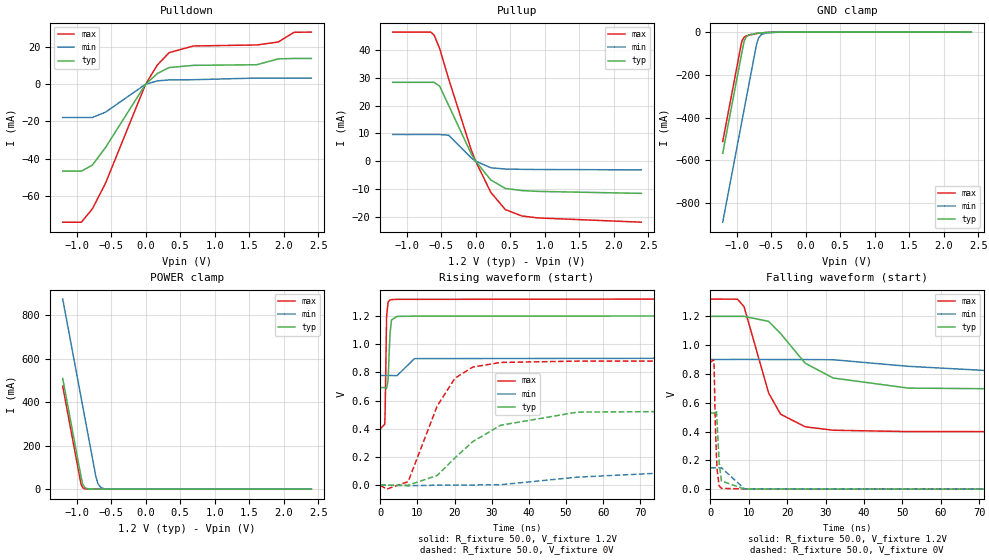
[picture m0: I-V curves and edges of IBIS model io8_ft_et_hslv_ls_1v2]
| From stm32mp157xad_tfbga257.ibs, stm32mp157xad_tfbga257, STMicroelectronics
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[Model]   io8_ft_et_hslv_ls_1v2
Model_type I/O
Polarity   Non-Inverting
Enable   Active-Low
| CAP_THRESHOLD on pad IOFT is "UDTCAPC" :
| Rising=20.00f vddiom   Falling=80.00f vddiom
| C_comp min and max val. don't necessarily correlate with the min and max pvt
| but are the smallest and greatest pad capacitance found.
| var   typ   min   max
C_comp   3.10945pF  3.08835pF  3.12935pF
|C_comp_pullup   1.82175pF  1.58940pF  1.75355pF
|C_comp_pulldown   1.28770pF  1.49895pF  1.37580pF
Vinl = 360.0mV
Vinh = 792.0mV
Vmeas = 600.0mV   | Reference voltage for timing measurements
Cref  = 50.0pF   | Timing specification test load capacitance value
Rref  = 100.0MOhm   | Timing specification test load resistance value
Vref  = 0V   | Timing specification test load voltage
[Model Spec]
| TIME_THRESHOLD on pin ZIV11 is "CMOS" :
| Rising=40.00f vdd   Falling=60.00f vdd
Vinl 463.60000mV 362.60000mV 506.60000mV
Vinh 741.40000mV 545.40000mV 817.40000mV
| variable   typ   min   max
[Temperature Range] 25.0 140.0 -40.0
| variable   typ   min   max
[Voltage Range] 1.2V 900.0mV 1.32V
| variable   typ   min   max
[POWER Clamp Reference] 1.2V 900.0mV 1.32V
| variable   typ   min   max
[GND Clamp Reference] 0V 0V 0V
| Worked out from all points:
|   slope of the pulldown table from 0 to 0.18 V, typ, clamps not added: 30 ohm
|   slope of the pullup table from 0 to 0.18 V, typ, clamps not added: 31.1 ohm
|   GND clamp passes 1 mA (typ) near -0.52 V on its own axis
|   POWER clamp passes 1 mA (typ) near -0.83 V on its own axis
|   rising waveform, R_fixture 50.0, V_fixture 1.2V: 20-80 % time 463ps typ, 1.28ns min, 297ps max; typ from 0.692 V to 1.2 V
|   falling waveform, R_fixture 50.0, V_fixture 1.2V: 20-80 % time 11.9ns typ, 29.9ns min, 6.05ns max; typ from 1.2 V to 0.692 V
|   rising waveform, R_fixture 50.0, V_fixture 0V: 20-80 % time 15.5ns typ, 35.5ns min, 8.51ns max; typ from 0 V to 0.529 V
|   falling waveform, R_fixture 50.0, V_fixture 0V: 20-80 % time 751ps typ, 1.47ns min, 598ps max; typ from 0.529 V to 0 V
[POWER Clamp]
-1.2V     508.8mA    874.1mA    473.5mA
-940mV    66.83mA    432.1mA    31.5mA
-930mV    49.83mA    415.1mA    19.15mA
-910mV    22.88mA    381.1mA    7.077mA
-880mV    7.117mA    330.1mA    1.59mA
-830mV    1.017mA    245.1mA    132uA
-720mV    14.05uA    58.12mA    554nA
-690mV    4.373uA    25.03mA    124.8nA
-650mV    922.5nA    8.136mA    17.23nA
-600mV    132.6nA    1.998mA    1.565nA
-490mV    2.857nA    90.92uA    111.8pA
2.4V      0A         0A         0A
[GND Clamp]
-1.2V     -567.2mA   -889.7mA   -512.2mA
-930mV    -108.2mA   -430.7mA   -53.23mA
-920mV    -91.21mA   -413.7mA   -40.49mA
-890mV    -43.51mA   -362.7mA   -23.59mA
-860mV    -22.57mA   -311.7mA   -17.89mA
-810mV    -12.11mA   -226.7mA   -13.23mA
-710mV    -6.053mA   -57.05mA   -7.064mA
-680mV    -4.908mA   -27.37mA   -5.632mA
-640mV    -3.605mA   -11.51mA   -3.985mA
-560mV    -1.665mA   -3.218mA   -1.61mA
-360mV    -34.72uA   -209.4uA   -9.248uA
2.4V      3.415nA    1.206uA    162.7pA
| variable   typ   min   max
[Pullup Reference] 1.2V 900.0mV 1.32V
| variable   typ   min   max
[Pulldown Reference] 0V 0V 0V
[Pullup]
-1.2V     28.34mA    9.569mA    46.41mA
-650mV    28.34mA    9.569mA    46.41mA
-600mV    28.34mA    9.569mA    45.32mA
-520mV    26.96mA    9.569mA    40.49mA
-390mV    20.06mA    9.313mA    29.59mA
-60mV     2.45mA     1.085mA    3.819mA
0V        5.9pA      1.254nA    2.839pA
220mV     -6.756mA   -2.387mA   -11.2mA
430mV     -9.815mA   -2.846mA   -17.42mA
670mV     -10.58mA   -2.948mA   -19.72mA
900mV     -10.88mA   -3.011mA   -20.42mA
2.4V      -11.6mA    -3.138mA   -21.96mA
[Pulldown]
-1.2V     -46.7mA    -17.86mA   -74.13mA
-930mV    -46.7mA    -17.86mA   -74.13mA
-770mV    -43.45mA   -17.86mA   -66.94mA
-580mV    -33.98mA   -14.99mA   -53.18mA
0V        0A         -6pA       0A
170mV     5.742mA    1.791mA    10.3mA
340mV     8.972mA    2.348mA    16.97mA
690mV     10.15mA    2.43mA     20.56mA
1.61V     10.49mA    3.332mA    21.11mA
1.92V     13.63mA    3.332mA    22.69mA
2.15V     13.87mA    3.332mA    27.93mA
2.4V      13.87mA    3.332mA    28.03mA
[Ramp]
dV/dt_r 317.3959mV/15.46923ns 89.16166mV/35.5467ns 528.12251mV/8.50615ns
dV/dt_f 304.64853mV/11.85118ns 73.17817mV/29.90312ns 552.41126mV/6.04586ns
R_load = 50.0
| Removed startup time: 0s 0s 0s  .
| Removed end time: 79.9ns.
[Rising Waveform]
R_fixture   = 50.0
V_fixture   = 1.2V
V_fixture_min = 900.0mV
V_fixture_max = 1.32V
0s        692.2mV    778.1mV    399.3mV
1.2ns     692.3mV    778.1mV    432.3mV
1.3ns     692.6mV    778.1mV    508.1mV
1.7ns     685.3mV    778.1mV    1.196V
2.1ns     745.8mV    778.1mV    1.299V
2.6ns     1.067V     778.1mV    1.313V
3ns       1.171V     778.1mV    1.316V
4.5ns     1.197V     776.4mV    1.318V
9.2ns     1.199V     897.5mV    1.318V
79.9ns    1.2V       899.9mV    1.32V
| Removed startup time: 0s 0s 0s  .
| Removed end time: 499.9ns.
[Falling Waveform]
R_fixture   = 50.0
V_fixture   = 1.2V
V_fixture_min = 900.0mV
V_fixture_max = 1.32V
0s        1.2V       900mV      1.32V
7.1ns     1.2V       900.8mV    1.319V
8.8ns     1.2V       901mV      1.267V
15.2ns    1.165V     900.1mV    666.7mV
18.3ns    1.081V     900mV      520.6mV
24.7ns    874.6mV    900mV      433.1mV
32ns      771.7mV    898.7mV    409.2mV
51.6ns    701.6mV    852.9mV    399.8mV
98.9ns    692.3mV    785.1mV    399.3mV
499.9ns   692.3mV    778mV      399.3mV
| Removed startup time: 0s 0s 0s  .
| Removed end time: 499.9ns.
[Rising Waveform]
R_fixture   = 50.0
V_fixture   = 0V
V_fixture_min = 0V
V_fixture_max = 0V
0s        -61.42nV   242.8nV    -3.809uV
1.7ns     -595.1uV   691.5nV    -28.55mV
7.5ns     -390.2uV   -4.45mV    24.63mV
15.3ns    68.29mV    -90.45uV   560.5mV
20.1ns    193.6mV    219.9uV    758.8mV
24.9ns    308.6mV    746.1uV    837.6mV
32.4ns    424.9mV    3.163mV    870.5mV
53.1ns    518.2mV    56.75mV    879.8mV
121.9ns   528.8mV    145.6mV    880.2mV
499.9ns   529mV      148.6mV    880.2mV
| Removed startup time: 0s 0s 0s  .
| Removed end time: 79.9ns.
[Falling Waveform]
R_fixture   = 50.0
V_fixture   = 0V
V_fixture_min = 0V
V_fixture_max = 0V
0s        529mV      148.7mV    880.2mV
900ps     529.3mV    148.7mV    898.7mV
1ns       529.1mV    148.7mV    852.4mV
1.3ns     533mV      148.7mV    460.6mV
1.6ns     547.2mV    148.7mV    235mV
1.8ns     453.4mV    148.7mV    131.1mV
2.3ns     189.2mV    148.7mV    23.75mV
2.9ns     57.04mV    148.6mV    6.151mV
8.9ns     813.1uV    2.608mV    1.267mV
79.9ns    4.406uV    42.18uV    -4.568uV
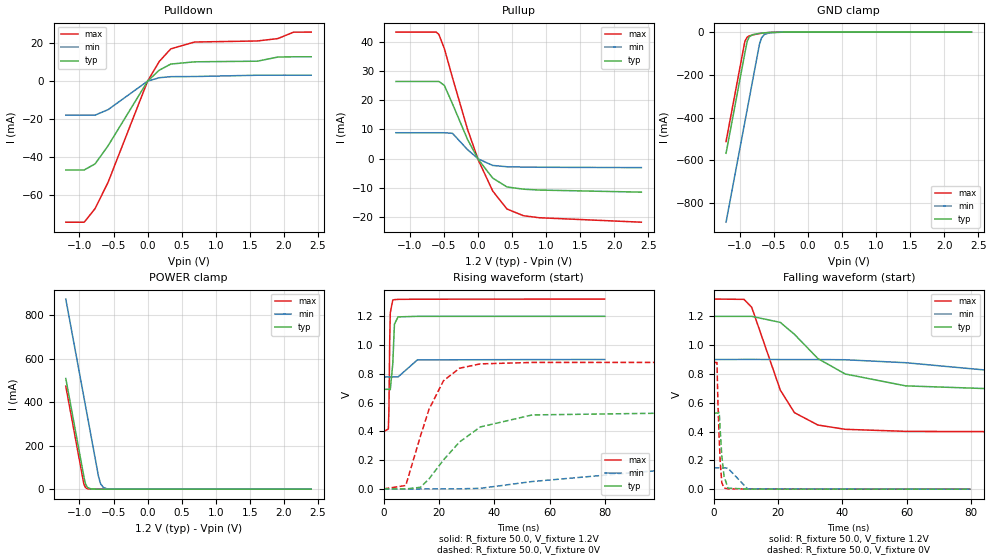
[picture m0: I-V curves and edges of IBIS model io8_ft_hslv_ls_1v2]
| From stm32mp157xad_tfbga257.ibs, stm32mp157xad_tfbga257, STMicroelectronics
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[Model]   io8_ft_hslv_ls_1v2
Model_type I/O
Polarity   Non-Inverting
Enable   Active-Low
| CAP_THRESHOLD on pad IOFT is "UDTCAPC" :
| Rising=20.00f vddiom   Falling=80.00f vddiom
| C_comp min and max val. don't necessarily correlate with the min and max pvt
| but are the smallest and greatest pad capacitance found.
| var   typ   min   max
C_comp   3.08865pF  3.06550pF  3.10825pF
|C_comp_pullup   1.81640pF  1.58310pF  1.74795pF
|C_comp_pulldown   1.27225pF  1.48240pF  1.36030pF
Vinl = 360.0mV
Vinh = 792.0mV
Vmeas = 600.0mV   | Reference voltage for timing measurements
Cref  = 50.0pF   | Timing specification test load capacitance value
Rref  = 100.0MOhm   | Timing specification test load resistance value
Vref  = 0V   | Timing specification test load voltage
[Model Spec]
| TIME_THRESHOLD on pin ZIV11 is "CMOS" :
| Rising=40.00f vdd   Falling=60.00f vdd
Vinl 463.60000mV 362.60000mV 506.60000mV
Vinh 741.40000mV 545.40000mV 817.40000mV
| variable   typ   min   max
[Temperature Range] 25.0 140.0 -40.0
| variable   typ   min   max
[Voltage Range] 1.2V 900.0mV 1.32V
| variable   typ   min   max
[POWER Clamp Reference] 1.2V 900.0mV 1.32V
| variable   typ   min   max
[GND Clamp Reference] 0V 0V 0V
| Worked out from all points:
|   slope of the pulldown table from 0 to 0.18 V, typ, clamps not added: 30 ohm
|   slope of the pullup table from 0 to 0.18 V, typ, clamps not added: 31.1 ohm
|   GND clamp passes 1 mA (typ) near -0.52 V on its own axis
|   POWER clamp passes 1 mA (typ) near -0.83 V on its own axis
|   rising waveform, R_fixture 50.0, V_fixture 1.2V: 20-80 % time 598ps typ, 1.65ns min, 350ps max; typ from 0.692 V to 1.2 V
|   falling waveform, R_fixture 50.0, V_fixture 1.2V: 20-80 % time 17.6ns typ, 43.1ns min, 8.86ns max; typ from 1.2 V to 0.692 V
|   rising waveform, R_fixture 50.0, V_fixture 0V: 20-80 % time 16.2ns typ, 35.6ns min, 9.39ns max; typ from 0 V to 0.528 V
|   falling waveform, R_fixture 50.0, V_fixture 0V: 20-80 % time 1.12ns typ, 2.35ns min, 846ps max; typ from 0.528 V to 0 V
[POWER Clamp]
-1.2V     508.8mA    874.1mA    473.5mA
-940mV    66.83mA    432.1mA    31.5mA
-930mV    49.83mA    415.1mA    19.15mA
-910mV    22.88mA    381.1mA    7.077mA
-880mV    7.117mA    330.1mA    1.59mA
-830mV    1.017mA    245.1mA    132uA
-720mV    14.05uA    58.12mA    554nA
-690mV    4.373uA    25.03mA    124.7nA
-650mV    922.4nA    8.136mA    17.22nA
-600mV    132.5nA    1.998mA    1.555nA
-490mV    2.736nA    90.9uA     103pA
2.4V      0A         0A         0A
[GND Clamp]
-1.2V     -567.2mA   -889.7mA   -512.2mA
-930mV    -108.2mA   -430.7mA   -53.23mA
-920mV    -91.21mA   -413.7mA   -40.49mA
-890mV    -43.51mA   -362.7mA   -23.59mA
-860mV    -22.57mA   -311.7mA   -17.89mA
-810mV    -12.11mA   -226.7mA   -13.23mA
-710mV    -6.053mA   -57.05mA   -7.064mA
-680mV    -4.908mA   -27.37mA   -5.632mA
-640mV    -3.605mA   -11.51mA   -3.985mA
-560mV    -1.665mA   -3.218mA   -1.61mA
-360mV    -34.72uA   -209.4uA   -9.248uA
2.4V      3.381nA    1.198uA    162.5pA
| variable   typ   min   max
[Pullup Reference] 1.2V 900.0mV 1.32V
| variable   typ   min   max
[Pulldown Reference] 0V 0V 0V
[Pullup]
-1.2V     26.54mA    8.882mA    43.55mA
-610mV    26.54mA    8.882mA    43.55mA
-570mV    26.54mA    8.882mA    42.74mA
-490mV    25.2mA     8.882mA    37.91mA
-370mV    18.81mA    8.672mA    27.82mA
-150mV    6.588mA    3.069mA    10.09mA
10mV      -383.3uA   -162.1uA   -605.9uA
220mV     -6.749mA   -2.383mA   -11.2mA
430mV     -9.803mA   -2.841mA   -17.41mA
670mV     -10.56mA   -2.943mA   -19.69mA
900mV     -10.86mA   -3.006mA   -20.39mA
2.4V      -11.58mA   -3.133mA   -21.93mA
[Pulldown]
-1.2V     -46.7mA    -17.86mA   -74.13mA
-930mV    -46.7mA    -17.86mA   -74.13mA
-770mV    -43.45mA   -17.86mA   -66.94mA
-580mV    -33.98mA   -14.99mA   -53.18mA
0V        0A         -3pA       0A
170mV     5.742mA    1.791mA    10.3mA
340mV     8.972mA    2.348mA    16.97mA
690mV     10.15mA    2.43mA     20.56mA
1.61V     10.49mA    3.107mA    21.11mA
1.91V     12.66mA    3.107mA    22.36mA
2.14V     12.8mA     3.107mA    25.73mA
2.4V      12.8mA     3.107mA    25.78mA
[Ramp]
dV/dt_r 316.98204mV/16.17336ns 89.01707mV/35.60268ns 527.833mV/9.39272ns
dV/dt_f 304.64461mV/17.62369ns 73.17368mV/43.1129ns 552.4115mV/8.85601ns
R_load = 50.0
| Removed startup time: 0s 0s 0s  .
| Removed end time: 79.9ns.
[Rising Waveform]
R_fixture   = 50.0
V_fixture   = 1.2V
V_fixture_min = 900.0mV
V_fixture_max = 1.32V
0s        692.2mV    778.1mV    399.3mV
1.7ns     692.4mV    778.1mV    416.2mV
1.9ns     692.3mV    778.1mV    539.1mV
2.2ns     691.5mV    778.1mV    1.04V
2.4ns     689.8mV    778.1mV    1.225V
3.3ns     871.2mV    778.1mV    1.313V
3.9ns     1.145V     778.1mV    1.316V
5.2ns     1.196V     778.1mV    1.318V
12.2ns    1.2V       897.2mV    1.319V
79.9ns    1.2V       899.9mV    1.32V
| Removed startup time: 0s 0s 0s  .
| Removed end time: 499.9ns.
[Falling Waveform]
R_fixture   = 50.0
V_fixture   = 1.2V
V_fixture_min = 900.0mV
V_fixture_max = 1.32V
0s        1.2V       900mV      1.32V
9.4ns     1.2V       900.8mV    1.318V
11.8ns    1.2V       900.9mV    1.263V
20.7ns    1.158V     900mV      687.9mV
25.1ns    1.075V     900mV      531.3mV
32.4ns    906.7mV    900mV      445.3mV
40.9ns    799.8mV    898.6mV    415.6mV
59.7ns    717.3mV    878mV      401.4mV
88.5ns    695.4mV    819.1mV    399.3mV
499.9ns   692.3mV    778mV      399.3mV
| Removed startup time: 0s 0s 0s  .
| Removed end time: 499.9ns.
[Rising Waveform]
R_fixture   = 50.0
V_fixture   = 0V
V_fixture_min = 0V
V_fixture_max = 0V
0s        73.05nV    737.4nV    -2.39uV
8ns       -430.3uV   -1.995mV   23.65mV
13.3ns    11.11mV    -432.9uV   366.8mV
16.4ns    69.31mV    -106.5uV   553.2mV
21.6ns    200.4mV    117.8uV    751.1mV
27.4ns    325.7mV    452.4uV    838.8mV
34.9ns    430.3mV    3.669mV    869.2mV
53.7ns    514.2mV    51.17mV    879.2mV
107ns     528.1mV    140.6mV    879.7mV
499.9ns   528.3mV    148.4mV    879.7mV
| Removed startup time: 0s 0s 0s  .
| Removed end time: 79.9ns.
[Falling Waveform]
R_fixture   = 50.0
V_fixture   = 0V
V_fixture_min = 0V
V_fixture_max = 0V
0s        528.3mV    148.4mV    879.7mV
1ns       528.4mV    148.4mV    879.3mV
1.3ns     528mV      148.4mV    593.2mV
1.7ns     532.9mV    148.4mV    343.6mV
2ns       410.7mV    148.4mV    190.2mV
2.5ns     229.7mV    148.4mV    45.74mV
3.2ns     90.24mV    148.3mV    7.314mV
4.4ns     7.202mV    145.6mV    2.088mV
10.5ns    594.3uV    2.606mV    1.234mV
79.9ns    5.325uV    82.6uV     42.19nV
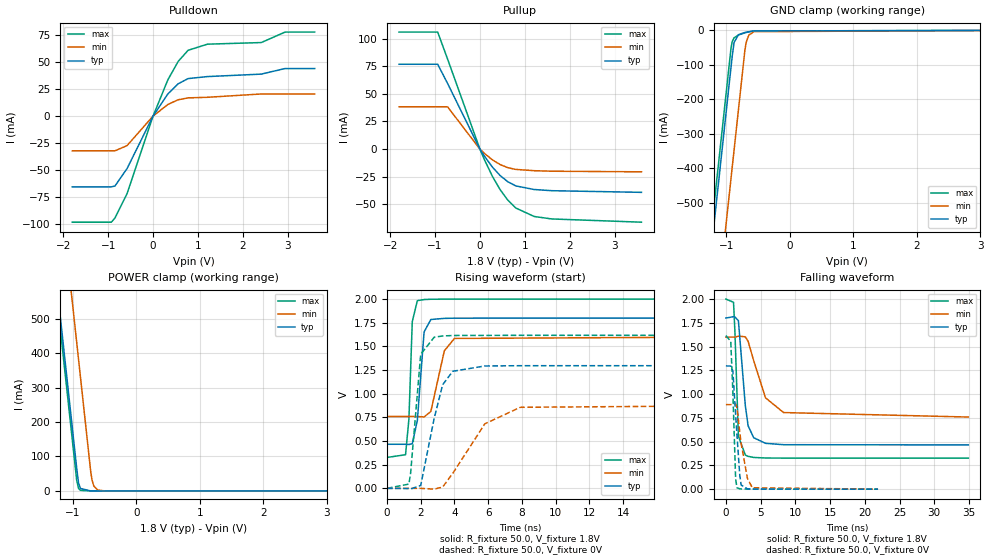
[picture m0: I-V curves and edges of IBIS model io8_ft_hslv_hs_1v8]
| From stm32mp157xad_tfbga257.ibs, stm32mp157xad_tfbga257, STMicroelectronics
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[Model]   io8_ft_hslv_hs_1v8
Model_type I/O
Polarity   Non-Inverting
Enable   Active-Low
| CAP_THRESHOLD on pad IOFT is "UDTCAPC" :
| Rising=20.00f vddiom   Falling=80.00f vddiom
| C_comp min and max val. don't necessarily correlate with the min and max pvt
| but are the smallest and greatest pad capacitance found.
| var   typ   min   max
C_comp   3.40998pF  3.40231pF  3.47825pF
|C_comp_pullup   1.96225pF  2.05415pF  1.91340pF
|C_comp_pulldown   1.44773pF  1.34816pF  1.56485pF
Vinl = 640.0mV
Vinh = 1.2V
Vmeas = 900.0mV   | Reference voltage for timing measurements
Cref  = 50.0pF   | Timing specification test load capacitance value
Rref  = 100.0MOhm   | Timing specification test load resistance value
Vref  = 0V   | Timing specification test load voltage
[Model Spec]
| TIME_THRESHOLD on pin ZIV11 is "CMOS" :
| Rising=40.00f vdd   Falling=60.00f vdd
Vinl 738.60000mV 665.60000mV 824.60000mV
Vinh 1.04640V 924.40000mV 1.13940V
| variable   typ   min   max
[Temperature Range] 25.0 140.0 -40.0
| variable   typ   min   max
[Voltage Range] 1.8V 1.6V 2.0V
| variable   typ   min   max
[POWER Clamp Reference] 1.8V 1.6V 2.0V
| variable   typ   min   max
[GND Clamp Reference] 0V 0V 0V
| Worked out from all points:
|   slope of the pulldown table from 0 to 0.27 V, typ, clamps not added: 16 ohm
|   slope of the pullup table from 0 to 0.27 V, typ, clamps not added: 17 ohm
|   GND clamp passes 1 mA (typ) near -0.52 V on its own axis
|   POWER clamp passes 1 mA (typ) near -0.83 V on its own axis
|   rising waveform, R_fixture 50.0, V_fixture 1.8V: 20-80 % time 316ps typ, 577ps min, 206ps max; typ from 0.466 V to 1.8 V
|   falling waveform, R_fixture 50.0, V_fixture 1.8V: 20-80 % time 895ps typ, 2.28ns min, 428ps max; typ from 1.8 V to 0.466 V
|   rising waveform, R_fixture 50.0, V_fixture 0V: 20-80 % time 886ps typ, 2.03ns min, 434ps max; typ from 0 V to 1.3 V
|   falling waveform, R_fixture 50.0, V_fixture 0V: 20-80 % time 706ps typ, 1.07ns min, 422ps max; typ from 1.3 V to 0 V
[POWER Clamp]
-1.8V     1.529A     1.894A     1.494A
-940mV    66.83mA    432.1mA    31.5mA
-910mV    22.88mA    381.1mA    7.077mA
-880mV    7.117mA    330.1mA    1.59mA
-720mV    14.05uA    58.12mA    554nA
-700mV    6.453uA    33.14mA    205nA
-670mV    2.008uA    14.27mA    46.28nA
-610mV    195.3nA    2.645mA    2.496nA
-500mV    3.825nA    120.4uA    129.9pA
3.6V      0A         0A         0A
[GND Clamp]
-1.8V     -1.588A    -1.91A     -1.533A
-1.26V    -670.3mA   -992.4mA   -614.9mA
-1.2V     -568.3mA   -890.4mA   -512.9mA
-930mV    -109.3mA   -431.4mA   -53.86mA
-910mV    -75.33mA   -397.4mA   -32.91mA
-880mV    -34.88mA   -346.4mA   -21.56mA
-810mV    -12.56mA   -227.4mA   -13.55mA
-710mV    -6.275mA   -57.63mA   -7.234mA
-690mV    -5.461mA   -35.21mA   -6.234mA
-650mV    -4.039mA   -14.43mA   -4.463mA
-570mV    -1.908mA   -3.832mA   -1.869mA
3.6V      5.036nA    1.588uA    245.5pA
| variable   typ   min   max
[Pullup Reference] 1.8V 1.6V 2.0V
| variable   typ   min   max
[Pulldown Reference] 0V 0V 0V
[Pullup]
-1.8V     76.86mA    38.28mA    106mA
-940mV    76.86mA    38.28mA    106mA
-720mV    59.49mA    38.28mA    81.6mA
0V        7.41pA     1.331nA    4.294pA
100mV     -6.394mA   -3.908mA   -9.529mA
280mV     -16.38mA   -9.808mA   -24.78mA
450mV     -23.93mA   -14.01mA   -36.72mA
620mV     -29.56mA   -16.84mA   -46.16mA
800mV     -33.39mA   -18.42mA   -53.41mA
1.21V     -36.65mA   -19.59mA   -61.09mA
1.6V      -37.71mA   -20.06mA   -63.31mA
3.6V      -39.21mA   -20.61mA   -66.25mA
[Pulldown]
-1.8V     -65.8mA    -32.31mA   -98.64mA
-930mV    -65.8mA    -32.31mA   -98.64mA
-850mV    -65.04mA   -32.31mA   -94.81mA
-580mV    -48.83mA   -27.49mA   -72.14mA
0V        0A         -2pA       0A
330mV     20.59mA    10.79mA    33.74mA
560mV     30.02mA    15.15mA    50.81mA
780mV     34.81mA    16.9mA     61.1mA
1.21V     36.69mA    17.44mA    66.81mA
2.41V     38.98mA    20.52mA    68.31mA
2.94V     44.17mA    20.52mA    78.04mA
3.6V      44.17mA    20.52mA    78.04mA
[Ramp]
dV/dt_r 777.74202mV/885.08357ps 533.91629mV/2.02828ns 970.01067mV/429.38377ps
dV/dt_f 800.5976mV/890.36148ps 504.71888mV/2.27422ns 1.00395V/423.14642ps
R_load = 50.0
| Removed startup time: 0s 0s 0s  .
| Removed end time: 21.9ns.
[Rising Waveform]
R_fixture   = 50.0
V_fixture   = 1.8V
V_fixture_min = 1.6V
V_fixture_max = 2.0V
0s        465.7mV    758.8mV    326.7mV
1.1ns     465.8mV    759mV      355.2mV
1.3ns     463.2mV    759.1mV    730.7mV
1.5ns     471.9mV    759.2mV    1.762V
1.8ns     717.3mV    759.1mV    1.983V
2.2ns     1.653V     754.3mV    1.995V
2.6ns     1.784V     812.9mV    1.998V
3.4ns     1.796V     1.453V     1.999V
4ns       1.798V     1.584V     2V
21.9ns    1.8V       1.6V       2V
| Removed startup time: 0s 0s 0s  .
| Removed end time: 34.9ns.
[Falling Waveform]
R_fixture   = 50.0
V_fixture   = 1.8V
V_fixture_min = 1.6V
V_fixture_max = 2.0V
0s        1.8V       1.6V       2V
1.1ns     1.815V     1.6V       1.966V
1.3ns     1.811V     1.599V     1.654V
1.8ns     1.773V     1.61V      557.6mV
2.8ns     875.8mV    1.603V     358.7mV
3.2ns     666.1mV    1.555V     345.3mV
4ns       541.4mV    1.352V     333.8mV
5.7ns     482.3mV    961.3mV    327.8mV
8.3ns     467.8mV    806mV      326.8mV
34.9ns    465.7mV    758.8mV    326.8mV
| Removed startup time: 0s 0s 0s  .
| Removed end time: 34.9ns.
[Rising Waveform]
R_fixture   = 50.0
V_fixture   = 0V
V_fixture_min = 0V
V_fixture_max = 0V
0s        -22.87nV   119.6nV    -3.298uV
1.3ns     -1.671mV   -9.335uV   45.23mV
1.4ns     -6.977mV   -4.753uV   159mV
2ns       31.03mV    90.39uV    1.417V
2.8ns     741.3mV    -8.512mV   1.597V
3.3ns     1.095V     14.41mV    1.61V
3.9ns     1.237V     158.7mV    1.615V
5.8ns     1.293V     682mV      1.616V
7.9ns     1.296V     856.5mV    1.617V
34.9ns    1.296V     889.9mV    1.617V
| Removed startup time: 0s 0s 0s  .
| Removed end time: 21.9ns.
[Falling Waveform]
R_fixture   = 50.0
V_fixture   = 0V
V_fixture_min = 0V
V_fixture_max = 0V
0s        1.296V     889.9mV    1.617V
700ps     1.296V     889.9mV    1.555V
1ns       1.246V     889.9mV    1.028V
1.4ns     784.2mV    895.2mV    109.3mV
1.6ns     564.9mV    854.1mV    14.39mV
2ns       143.6mV    600.5mV    3.632mV
2.2ns     43.47mV    478.9mV    2.733mV
3.1ns     3.072mV    114.6mV    980.4uV
3.8ns     1.612mV    14.47mV    494.6uV
21.9ns    1.333uV    6.536uV    200.7nV
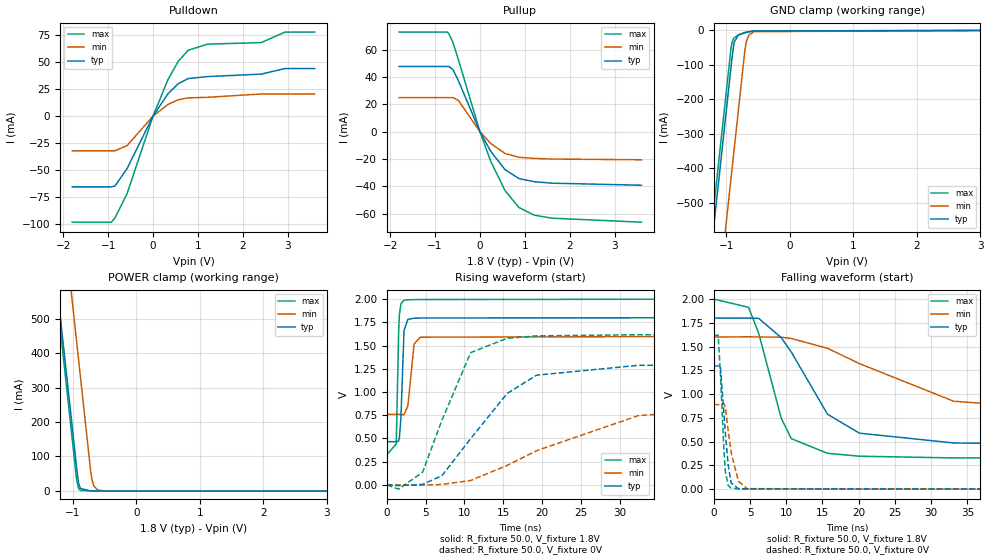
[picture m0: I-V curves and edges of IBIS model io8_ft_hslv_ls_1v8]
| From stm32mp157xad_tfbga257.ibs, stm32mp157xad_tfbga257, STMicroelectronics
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[Model]   io8_ft_hslv_ls_1v8
Model_type I/O
Polarity   Non-Inverting
Enable   Active-Low
| CAP_THRESHOLD on pad IOFT is "UDTCAPC" :
| Rising=20.00f vddiom   Falling=80.00f vddiom
| C_comp min and max val. don't necessarily correlate with the min and max pvt
| but are the smallest and greatest pad capacitance found.
| var   typ   min   max
C_comp   3.40998pF  3.40231pF  3.47825pF
|C_comp_pullup   1.96225pF  2.05415pF  1.91340pF
|C_comp_pulldown   1.44773pF  1.34816pF  1.56485pF
Vinl = 640.0mV
Vinh = 1.2V
Vmeas = 900.0mV   | Reference voltage for timing measurements
Cref  = 50.0pF   | Timing specification test load capacitance value
Rref  = 100.0MOhm   | Timing specification test load resistance value
Vref  = 0V   | Timing specification test load voltage
[Model Spec]
| TIME_THRESHOLD on pin ZIV11 is "CMOS" :
| Rising=40.00f vdd   Falling=60.00f vdd
Vinl 738.60000mV 665.60000mV 824.60000mV
Vinh 1.04640V 924.40000mV 1.13940V
| variable   typ   min   max
[Temperature Range] 25.0 140.0 -40.0
| variable   typ   min   max
[Voltage Range] 1.8V 1.6V 2.0V
| variable   typ   min   max
[POWER Clamp Reference] 1.8V 1.6V 2.0V
| variable   typ   min   max
[GND Clamp Reference] 0V 0V 0V
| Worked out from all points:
|   slope of the pulldown table from 0 to 0.27 V, typ, clamps not added: 16 ohm
|   slope of the pullup table from 0 to 0.27 V, typ, clamps not added: 17 ohm
|   GND clamp passes 1 mA (typ) near -0.52 V on its own axis
|   POWER clamp passes 1 mA (typ) near -0.83 V on its own axis
|   rising waveform, R_fixture 50.0, V_fixture 1.8V: 20-80 % time 290ps typ, 520ps min, 237ps max; typ from 0.466 V to 1.8 V
|   falling waveform, R_fixture 50.0, V_fixture 1.8V: 20-80 % time 6.49ns typ, 15.7ns min, 3.61ns max; typ from 1.8 V to 0.466 V
|   rising waveform, R_fixture 50.0, V_fixture 0V: 20-80 % time 7.46ns typ, 15.8ns min, 4.19ns max; typ from 0 V to 1.3 V
|   falling waveform, R_fixture 50.0, V_fixture 0V: 20-80 % time 807ps typ, 1.14ns min, 598ps max; typ from 1.3 V to 0 V
[POWER Clamp]
-1.8V     1.529A     1.894A     1.494A
-940mV    66.83mA    432.1mA    31.5mA
-910mV    22.88mA    381.1mA    7.077mA
-880mV    7.117mA    330.1mA    1.59mA
-720mV    14.05uA    58.12mA    554nA
-700mV    6.453uA    33.14mA    205nA
-670mV    2.008uA    14.27mA    46.28nA
-610mV    195.3nA    2.645mA    2.496nA
-500mV    3.825nA    120.4uA    129.9pA
3.6V      0A         0A         0A
[GND Clamp]
-1.8V     -1.588A    -1.91A     -1.533A
-1.26V    -670.3mA   -992.4mA   -614.9mA
-1.2V     -568.3mA   -890.4mA   -512.9mA
-930mV    -109.3mA   -431.4mA   -53.86mA
-910mV    -75.33mA   -397.4mA   -32.91mA
-880mV    -34.88mA   -346.4mA   -21.56mA
-810mV    -12.56mA   -227.4mA   -13.55mA
-710mV    -6.275mA   -57.63mA   -7.234mA
-690mV    -5.461mA   -35.21mA   -6.234mA
-650mV    -4.039mA   -14.43mA   -4.463mA
-570mV    -1.908mA   -3.832mA   -1.869mA
3.6V      5.036nA    1.588uA    245.5pA
| variable   typ   min   max
[Pullup Reference] 1.8V 1.6V 2.0V
| variable   typ   min   max
[Pulldown Reference] 0V 0V 0V
[Pullup]
-1.8V     47.63mA    24.9mA     72.78mA
-730mV    47.63mA    24.9mA     72.78mA
-690mV    47.63mA    24.9mA     71.57mA
-600mV    45.37mA    24.9mA     65.1mA
-480mV    37.34mA    22.87mA    52.75mA
0V        7.41pA     1.331nA    4.294pA
240mV     -14.34mA   -8.624mA   -21.61mA
560mV     -27.8mA    -16mA      -43.11mA
870mV     -34.35mA   -18.76mA   -55.49mA
1.21V     -36.65mA   -19.59mA   -61.09mA
1.6V      -37.71mA   -20.06mA   -63.31mA
3.6V      -39.21mA   -20.61mA   -66.25mA
[Pulldown]
-1.8V     -65.8mA    -32.31mA   -98.64mA
-930mV    -65.8mA    -32.31mA   -98.64mA
-850mV    -65.04mA   -32.31mA   -94.81mA
-580mV    -48.83mA   -27.49mA   -72.14mA
0V        0A         -2pA       0A
330mV     20.59mA    10.79mA    33.74mA
560mV     30.02mA    15.15mA    50.81mA
780mV     34.81mA    16.9mA     61.1mA
1.21V     36.69mA    17.44mA    66.81mA
2.41V     38.98mA    20.51mA    68.31mA
2.94V     44.17mA    20.51mA    78.04mA
3.6V      44.17mA    20.51mA    78.04mA
[Ramp]
dV/dt_r 777.75174mV/7.46009ns 533.88892mV/15.81359ns 970.01446mV/4.19376ns
dV/dt_f 800.59769mV/6.48971ns 504.70755mV/15.73502ns 1.00395V/3.60949ns
R_load = 50.0
| Removed startup time: 0s 0s 0s  .
| Removed end time: 54.9ns.
[Rising Waveform]
R_fixture   = 50.0
V_fixture   = 1.8V
V_fixture_min = 1.6V
V_fixture_max = 2.0V
0s        465.7mV    758.8mV    326.7mV
1.2ns     465.2mV    758.9mV    441.8mV
1.5ns     472.5mV    759mV      1.629V
1.6ns     505.3mV    758.9mV    1.829V
1.8ns     717.4mV    758.7mV    1.95V
2.2ns     1.662V     754.7mV    1.987V
2.7ns     1.782V     853.7mV    1.992V
3.5ns     1.794V     1.517V     1.994V
4.3ns     1.796V     1.59V      1.995V
54.9ns    1.8V       1.6V       2V
| Removed startup time: 0s 0s 0s  .
| Removed end time: 364.9ns.
[Falling Waveform]
R_fixture   = 50.0
V_fixture   = 1.8V
V_fixture_min = 1.6V
V_fixture_max = 2.0V
0s        1.8V       1.6V       2V
4.8ns     1.8V       1.603V     1.913V
6.2ns     1.797V     1.601V     1.64V
9.3ns     1.595V     1.599V     748.8mV
10.7ns    1.442V     1.585V     531.3mV
15.7ns    788mV      1.482V     377.3mV
20.1ns    589.1mV    1.321V     346.8mV
33.1ns    486.2mV    925.2mV    328.7mV
58.4ns    466.8mV    781.8mV    326.8mV
364.9ns   465.7mV    758.8mV    326.7mV
| Removed startup time: 0s 0s 0s  .
| Removed end time: 364.9ns.
[Rising Waveform]
R_fixture   = 50.0
V_fixture   = 0V
V_fixture_min = 0V
V_fixture_max = 0V
0s        121.1nV    205.2nV    -3.013uV
1.5ns     -7.557mV   5.524uV    -45.43mV
4.6ns     5.784mV    -1.439mV   137.6mV
7.1ns     100.5mV    5.302mV    698.5mV
10.8ns    498.3mV    48.08mV    1.424V
15.5ns    984mV      209.7mV    1.578V
19.3ns    1.181V     368.8mV    1.604V
32.4ns    1.287V     745.1mV    1.616V
51.8ns    1.296V     872.9mV    1.617V
364.9ns   1.296V     889.8mV    1.617V
| Removed startup time: 0s 0s 0s  .
| Removed end time: 54.9ns.
[Falling Waveform]
R_fixture   = 50.0
V_fixture   = 0V
V_fixture_min = 0V
V_fixture_max = 0V
0s        1.296V     889.9mV    1.617V
600ps     1.296V     889.9mV    1.621V
900ps     1.301V     889.9mV    1.236V
1.4ns     797.4mV    898.1mV    411.5mV
1.6ns     589mV      860.7mV    186mV
2ns       249.5mV    607.6mV    36.14mV
2.4ns     66.07mV    384.6mV    10.47mV
3.4ns     4.832mV    84.22mV    3.886mV
4.6ns     2.327mV    5.113mV    3.665mV
54.9ns    -1.485uV   39.03uV    -12.43uV
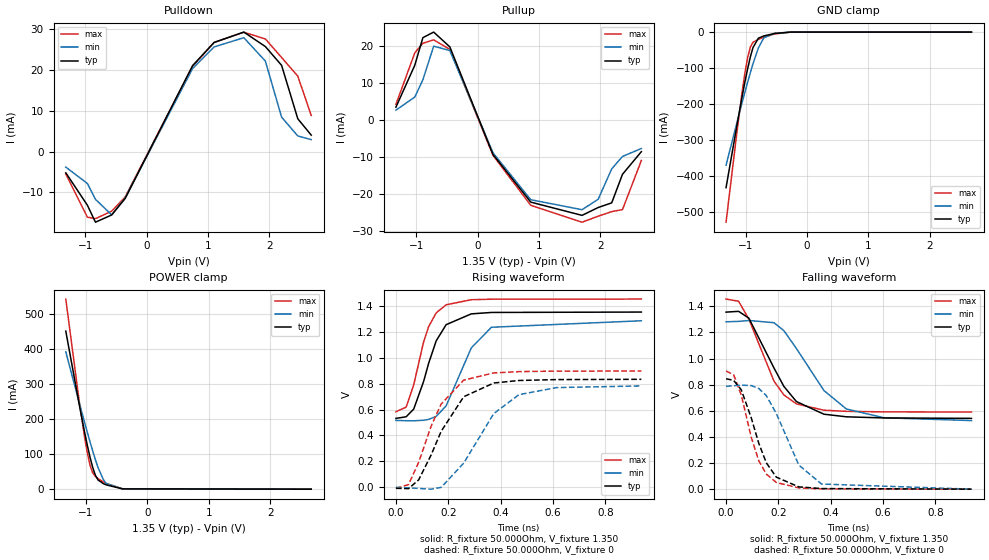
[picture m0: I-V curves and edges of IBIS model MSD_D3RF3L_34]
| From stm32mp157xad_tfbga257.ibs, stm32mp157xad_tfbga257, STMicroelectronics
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[Model] MSD_D3RF3L_34
Model_type   I/O
C_comp 2.247pF   2.166pF   2.364pF
Vinh = 810.000mV
Vinl = 540.000mV
Vmeas = 675.000mV
Vref = 675.000mV
[Model Spec]
Vinh   810.000mV   777.000mV   860.000mV
Vinl   540.000mV   507.000mV   590.000mV
Vmeas   675.000mV   642.000mV   725.000mV
Vref   675.000mV   642.000mV   725.000mV
[Temperature Range]   25.000   125.000   -40.000
[Voltage Range]   1.350V   1.283V   1.450V
[GND Clamp Reference]   0.00V   0.00V   0.00V
[Pulldown Reference]   0.00V   0.00V   0.00V
[POWER Clamp Reference]   1.350V   1.283V   1.450V
[Pullup Reference]   1.350V   1.283V   1.450V
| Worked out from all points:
|   slope of the pulldown table from 0 to 0.203 V, typ, clamps not added: 31 ohm
|   slope of the pullup table from 0 to 0.203 V, typ, clamps not added: 26.2 ohm
|   GND clamp passes 1 mA (typ) near -0.41 V on its own axis
|   POWER clamp passes 1 mA (typ) near -0.41 V on its own axis
|   rising waveform, R_fixture 50.000Ohm, V_fixture 1.350: 20-80 % time 80.7ps typ, 102ps min, 70.2ps max; typ from 0.532 V to 1.35 V
|   rising waveform, R_fixture 50.000Ohm, V_fixture 0: 20-80 % time 128ps typ, 151ps min, 113ps max; typ from -0.006 V to 0.832 V
|   falling waveform, R_fixture 50.000Ohm, V_fixture 1.350: 20-80 % time 129ps typ, 161ps min, 113ps max; typ from 1.36 V to 0.542 V
|   falling waveform, R_fixture 50.000Ohm, V_fixture 0: 20-80 % time 87.1ps typ, 107ps min, 76ps max; typ from 0.846 V to 0 V
[GND Clamp]
-1.318V   -432.8mA   -370.3mA   -528.8mA
-1.142V   -260.6mA   -252.7mA   -280.2mA
-1.055V   -178.2mA   -195.3mA   -165.2mA
-1.011V   -139.1mA   -167.2mA   -114.1mA
-966.7mV  -102.4mA   -139.8mA   -71.26mA
-922.7mV  -69.52mA   -113.2mA   -41.65mA
-878.8mV  -42.91mA   -87.93mA   -28.28mA
-790.9mV  -16.85mA   -43.88mA   -20.2mA
-703mV    -10.77mA   -15.98mA   -14.6mA
-527.3mV  -3.882mA   -3.287mA   -5.181mA
-263.6mV  -34.33uA   -68.91uA   -22.73uA
2.68V     23.22nA    650.7nA    2.894nA
[Power Clamp]
-1.33V    452.1mA    392.8mA    543.8mA
-1.111V   241.8mA    247.2mA    250.6mA
-1.023V   162.2mA    190.3mA    147.9mA
-978.8mV  125.1mA    162.4mA    103.4mA
-934.9mV  91.03mA    135.1mA    67.95mA
-890.9mV  61.68mA    108.8mA    46.37mA
-847mV    39.38mA    83.87mA    35.91mA
-803mV    26.06mA    61.08mA    29.87mA
-715.1mV  15.46mA    26.37mA    20.47mA
-671.2mV  12.27mA    16.31mA    16.36mA
-407.6mV  879.9uA    1.157mA    1.067mA
2.668V    -39.9nA    -766.6nA   -3.595nA
[Pulldown]
-1.318V   -5.2mA     -3.8mA     -5.5mA
-966.7mV  -13.1mA    -7.8mA     -16.02mA
-834.9mV  -17.25mA   -11.67mA   -16.39mA
-571.2mV  -15.49mA   -15.46mA   -14.56mA
-351.5mV  -11.48mA   -11.33mA   -11.11mA
747mV     20.95mA    20.23mA    20.78mA
1.098V    26.62mA    25.53mA    26.63mA
1.582V    29.15mA    27.78mA    29.12mA
1.933V    25.62mA    22.07mA    27.47mA
2.197V    21.04mA    8.4mA      22.95mA
2.461V    8mA        3.8mA      18.4mA
2.68V     4mA        2.9mA      8.8mA
[Pullup]
-1.33V    3.4mA      2.605mA    4.152mA
-1.023V   14.7mA     6.125mA    18.04mA
-890.9mV  22.16mA    10.79mA    20.65mA
-715.1mV  23.66mA    19.86mA    21.56mA
-451.5mV  19.66mA    18.68mA    18.99mA
251.5mV   -9.374mA   -8.925mA   -9.602mA
866.7mV   -22.22mA   -21.57mA   -23.09mA
1.702V    -25.79mA   -24.26mA   -27.63mA
1.965V    -23.67mA   -21.43mA   -26.01mA
2.185V    -22.41mA   -13.25mA   -24.77mA
2.361V    -14.7mA    -9.89mA    -24.24mA
2.668V    -8.6mA     -7.748mA   -10.98mA
[Ramp]
R_load=50.000Ohm
dV/dt_r   492.120mV/104.000ps  462.689mV/127.500ps  526.590mV/91.500ps
dV/dt_f   492.120mV/108.500ps  462.689mV/134.500ps  526.590mV/95.000ps
[Rising waveform]
R_fixture=50.000Ohm
V_fixture=1.350
V_fixture_min=1.283
V_fixture_max=1.450
0s        531.8mV    516.3mV    582.5mV
39ps      544mV      513.9mV    618.4mV
68ps      603.2mV    513.3mV    790.3mV
106ps     817mV      517.4mV    1.122V
125ps     955.5mV    523.9mV    1.238V
154ps     1.129V     547.3mV    1.344V
192ps     1.253V     628.6mV    1.406V
288ps     1.336V     1.074V     1.445V
365ps     1.347V     1.233V     1.449V
938ps     1.35V      1.283V     1.45V
[Rising waveform]
R_fixture=50.000Ohm
V_fixture=0
0s        -6.256mV   484.9uV    -5.867mV
48ps      -9.045mV   -2.442mV   21.85mV
87ps      58.8mV     -7.485mV   194.1mV
135ps     252.5mV    -13.02mV   474.6mV
173ps     432.5mV    805.1uV    642.3mV
259ps     698.4mV    187.4mV    826.1mV
374ps     804mV      568.7mV    881.8mV
470ps     823.4mV    714.2mV    891.5mV
614ps     830.3mV    768.7mV    895.5mV
938ps     832.4mV    781.6mV    896.1mV
[Falling waveform]
R_fixture=50.000Ohm
V_fixture=1.350
V_fixture_min=1.283
V_fixture_max=1.450
0s        1.356V     1.282V     1.456V
48ps      1.362V     1.285V     1.439V
87ps      1.31V      1.292V     1.303V
183ps     928.9mV    1.275V     828mV
221ps     787mV      1.214V     722.1mV
269ps     670.9mV    1.077V     653.2mV
374ps     574.2mV    755.5mV    604.7mV
460ps     554.2mV    614mV      596.1mV
604ps     545.5mV    546.6mV    591.9mV
938ps     542.2mV    525.4mV    590.8mV
[Falling waveform]
R_fixture=50.000Ohm
V_fixture=0
0s        845.7mV    787.6mV    905.6mV
29ps      833.2mV    792.3mV    876.1mV
58ps      761.6mV    796.6mV    722.5mV
96ps      548.4mV    793.6mV    399.7mV
125ps     351.7mV    771.2mV    217.4mV
154ps     201.7mV    716.3mV    115.6mV
192ps     92.26mV    580.1mV    51.25mV
278ps     17.66mV    185mV      9.684mV
365ps     4.566mV    39.23mV    1.942mV
938ps     5.746uV    57.05uV    3.826uV
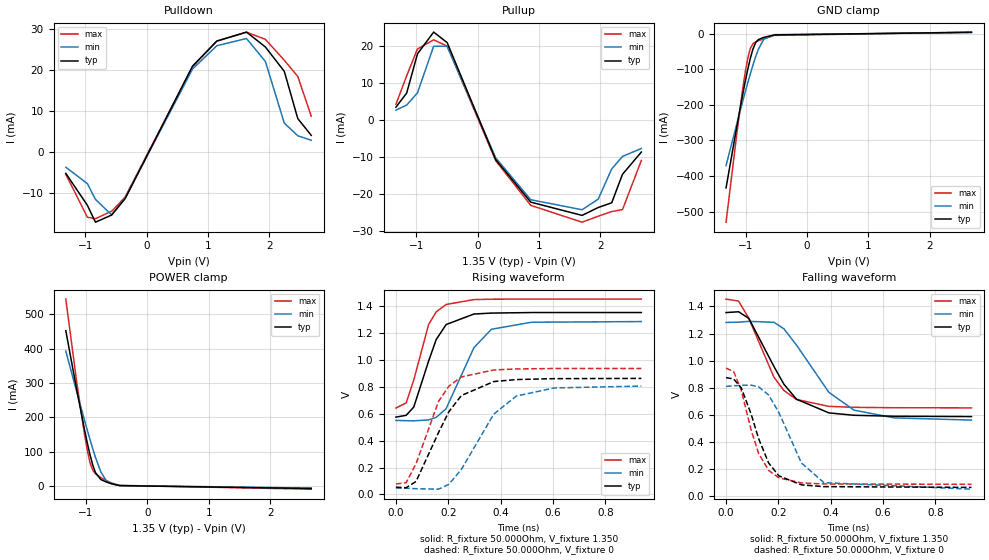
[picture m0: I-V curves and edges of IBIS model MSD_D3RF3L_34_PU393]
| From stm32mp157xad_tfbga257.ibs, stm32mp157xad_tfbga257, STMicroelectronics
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[Model] MSD_D3RF3L_34_PU393
Model_type   I/O
C_comp 2.367pF   2.282pF   2.491pF
Vinh = 810.000mV
Vinl = 540.000mV
Vmeas = 675.000mV
Vref = 675.000mV
[Model Spec]
Vinh   810.000mV   777.000mV   860.000mV
Vinl   540.000mV   507.000mV   590.000mV
Vmeas   675.000mV   642.000mV   725.000mV
Vref   675.000mV   642.000mV   725.000mV
[Temperature Range]   25.000   125.000   -40.000
[Voltage Range]   1.350V   1.283V   1.450V
[GND Clamp Reference]   0.00V   0.00V   0.00V
[Pulldown Reference]   0.00V   0.00V   0.00V
[POWER Clamp Reference]   1.350V   1.283V   1.450V
[Pullup Reference]   1.350V   1.283V   1.450V
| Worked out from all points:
|   slope of the pulldown table from 0 to 0.203 V, typ, clamps not added: 31 ohm
|   slope of the pullup table from 0 to 0.203 V, typ, clamps not added: 26.2 ohm
|   GND clamp passes 1 mA (typ) near -0.41 V on its own axis
|   POWER clamp passes 1 mA (typ) near -0.41 V on its own axis
|   rising waveform, R_fixture 50.000Ohm, V_fixture 1.350: 20-80 % time 80.5ps typ, 103ps min, 69.9ps max; typ from 0.574 V to 1.35 V
|   rising waveform, R_fixture 50.000Ohm, V_fixture 0: 20-80 % time 122ps typ, 147ps min, 105ps max; typ from 0.054 V to 0.861 V
|   falling waveform, R_fixture 50.000Ohm, V_fixture 1.350: 20-80 % time 133ps typ, 165ps min, 115ps max; typ from 1.35 V to 0.585 V
|   falling waveform, R_fixture 50.000Ohm, V_fixture 0: 20-80 % time 90.9ps typ, 112ps min, 78.9ps max; typ from 0.874 V to 0.061 V
[GND Clamp]
-1.318V   -433mA     -370.4mA   -529.2mA
-1.142V   -260.8mA   -252.9mA   -280.4mA
-1.055V   -178.3mA   -195.3mA   -165.4mA
-1.011V   -139.2mA   -167.3mA   -114.3mA
-966.7mV  -102.4mA   -139.8mA   -71.44mA
-922.7mV  -69.62mA   -113.3mA   -41.82mA
-878.8mV  -43.01mA   -87.99mA   -28.44mA
-834.9mV  -25.43mA   -64.57mA   -23.51mA
-790.9mV  -16.93mA   -43.94mA   -20.33mA
-703mV    -10.83mA   -16.02mA   -14.7mA
-527.3mV  -3.907mA   -3.3mA     -5.218mA
2.68V     3.366mA    2.86mA     3.981mA
[Power Clamp]
-1.33V    452.4mA    393mA      544.2mA
-1.155V   283.3mA    276.3mA    306.7mA
-1.023V   162.4mA    190.5mA    148.2mA
-978.8mV  125.2mA    162.6mA    103.6mA
-934.9mV  91.22mA    135.3mA    68.17mA
-890.9mV  61.85mA    109mA      46.56mA
-847mV    39.54mA    84.01mA    36.1mA
-759.1mV  19.58mA    41.61mA    25.09mA
-671.2mV  12.36mA    16.39mA    16.46mA
-583.3mV  7.075mA    7.103mA    9.355mA
-451.5mV  1.823mA    2.063mA    2.279mA
2.668V    -6.637mA   -5.319mA   -8.53mA
[Pulldown]
-1.318V   -5.3mA     -3.8mA     -5.5mA
-966.7mV  -13.1mA    -7.8mA     -16.02mA
-834.9mV  -17.24mA   -11.68mA   -16.38mA
-571.2mV  -15.49mA   -15.46mA   -14.57mA
-351.5mV  -11.48mA   -11.33mA   -11.1mA
747mV     20.94mA    20.22mA    20.78mA
1.142V    27.05mA    25.92mA    27.05mA
1.626V    29.25mA    27.68mA    29.23mA
1.933V    25.61mA    22.07mA    27.48mA
2.241V    19.66mA    7mA        22.36mA
2.461V    8.1mA      3.9mA      18.4mA
2.68V     4mA        2.8mA      8.7mA
[Pullup]
-1.33V    3.4mA      2.605mA    4.152mA
-1.155V   7.2mA      3.962mA    11.86mA
-978.8mV  17.8mA     7.282mA    19.12mA
-715.1mV  23.66mA    19.86mA    21.56mA
-495.5mV  20.82mA    19.82mA    19.89mA
295.4mV   -10.76mA   -10.27mA   -11.02mA
866.7mV   -22.22mA   -21.57mA   -23.09mA
1.702V    -25.8mA    -24.27mA   -27.63mA
1.965V    -23.67mA   -21.42mA   -26.02mA
2.185V    -22.4mA    -13.26mA   -24.76mA
2.361V    -14.7mA    -9.885mA   -24.24mA
2.668V    -8.7mA     -7.748mA   -10.98mA
[Ramp]
R_load=50.000Ohm
dV/dt_r   469.725mV/100.500ps  445.260mV/125.000ps  495.603mV/87.500ps
dV/dt_f   469.725mV/112.000ps  445.257mV/139.500ps  495.603mV/97.500ps
[Rising waveform]
R_fixture=50.000Ohm
V_fixture=1.350
V_fixture_min=1.283
V_fixture_max=1.450
0s        574.3mV    549.9mV    641.4mV
39ps      587.4mV    547.4mV    679.1mV
68ps      647.9mV    546.4mV    848.2mV
125ps     990.1mV    553.6mV    1.261V
154ps     1.15V      572.2mV    1.355V
192ps     1.261V     637.4mV    1.41V
298ps     1.339V     1.089V     1.446V
365ps     1.346V     1.226V     1.449V
518ps     1.35V      1.278V     1.45V
938ps     1.35V      1.283V     1.45V
[Rising waveform]
R_fixture=50.000Ohm
V_fixture=0
0s        54.48mV    47.79mV    78.01mV
39ps      50.05mV    46.18mV    87.56mV
77ps      96.99mV    42.73mV    228.4mV
163ps     460.4mV    39.49mV    691.2mV
202ps     613.3mV    74.93mV    802.6mV
250ps     734.1mV    185.5mV    872.4mV
374ps     838mV      596.4mV    923.9mV
460ps     852.8mV    730.2mV    931.5mV
604ps     859.5mV    790.4mV    934.7mV
938ps     861.2mV    804.4mV    935.1mV
[Falling waveform]
R_fixture=50.000Ohm
V_fixture=1.350
V_fixture_min=1.283
V_fixture_max=1.450
0s        1.355V     1.282V     1.455V
48ps      1.361V     1.284V     1.44V
87ps      1.312V     1.29V      1.312V
183ps     955.9mV    1.283V     876.4mV
221ps     825mV      1.235V     778.4mV
269ps     714.1mV    1.115V     711.8mV
393ps     612.3mV    764.5mV    660.6mV
489ps     594.6mV    632.7mV    653.5mV
642ps     587.6mV    575.4mV    650.5mV
938ps     585mV      559mV      649.5mV
[Falling waveform]
R_fixture=50.000Ohm
V_fixture=0
0s        873.6mV    808.5mV    943.7mV
29ps      863mV      812.5mV    919.1mV
58ps      798.6mV    816.9mV    781.6mV
96ps      602.7mV    817.7mV    484.3mV
125ps     419mV      804.3mV    309.5mV
163ps     240.6mV    744.3mV    186mV
202ps     146.2mV    614.5mV    131.1mV
288ps     79.64mV    241.9mV    93.78mV
374ps     66.35mV    95.91mV    85.98mV
938ps     60.77mV    47.63mV    83.7mV
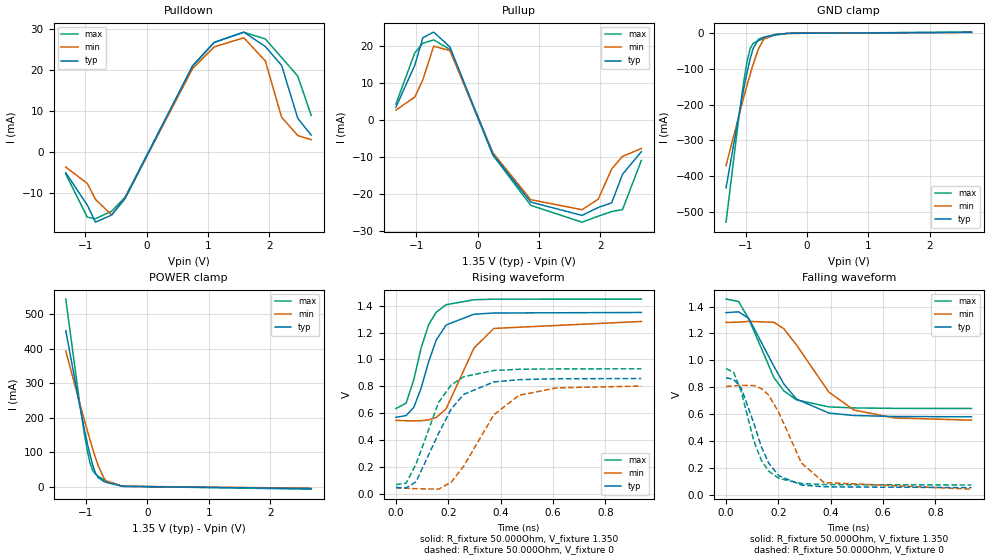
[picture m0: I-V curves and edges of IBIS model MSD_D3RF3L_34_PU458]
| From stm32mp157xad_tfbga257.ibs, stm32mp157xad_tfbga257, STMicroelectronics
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[Model] MSD_D3RF3L_34_PU458
Model_type   I/O
C_comp 2.396pF   2.311pF   2.520pF
Vinh = 810.000mV
Vinl = 540.000mV
Vmeas = 675.000mV
Vref = 675.000mV
[Model Spec]
Vinh   810.000mV   777.000mV   860.000mV
Vinl   540.000mV   507.000mV   590.000mV
Vmeas   675.000mV   642.000mV   725.000mV
Vref   675.000mV   642.000mV   725.000mV
[Temperature Range]   25.000   125.000   -40.000
[Voltage Range]   1.350V   1.283V   1.450V
[GND Clamp Reference]   0.00V   0.00V   0.00V
[Pulldown Reference]   0.00V   0.00V   0.00V
[POWER Clamp Reference]   1.350V   1.283V   1.450V
[Pullup Reference]   1.350V   1.283V   1.450V
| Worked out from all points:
|   slope of the pulldown table from 0 to 0.203 V, typ, clamps not added: 31 ohm
|   slope of the pullup table from 0 to 0.203 V, typ, clamps not added: 26.2 ohm
|   GND clamp passes 1 mA (typ) near -0.40 V on its own axis
|   POWER clamp passes 1 mA (typ) near -0.41 V on its own axis
|   rising waveform, R_fixture 50.000Ohm, V_fixture 1.350: 20-80 % time 81.3ps typ, 104ps min, 70.7ps max; typ from 0.568 V to 1.35 V
|   rising waveform, R_fixture 50.000Ohm, V_fixture 0: 20-80 % time 124ps typ, 149ps min, 108ps max; typ from 0.046 V to 0.857 V
|   falling waveform, R_fixture 50.000Ohm, V_fixture 1.350: 20-80 % time 134ps typ, 166ps min, 117ps max; typ from 1.35 V to 0.579 V
|   falling waveform, R_fixture 50.000Ohm, V_fixture 0: 20-80 % time 91.4ps typ, 112ps min, 79.5ps max; typ from 0.87 V to 0.052 V
[GND Clamp]
-1.318V   -433.3mA   -370.7mA   -529.5mA
-1.142V   -261mA     -253.1mA   -280.7mA
-1.055V   -178.6mA   -195.5mA   -165.6mA
-1.011V   -139.4mA   -167.5mA   -114.5mA
-966.7mV  -102.7mA   -139.9mA   -71.66mA
-922.7mV  -69.78mA   -113.4mA   -42.02mA
-878.8mV  -43.16mA   -88.12mA   -28.62mA
-790.9mV  -17.05mA   -44.03mA   -20.47mA
-703mV    -10.93mA   -16.1mA    -14.81mA
-527.3mV  -3.949mA   -3.336mA   -5.27mA
-307.6mV  -123uA     -180.2uA   -110uA
2.68V     2.885mA    2.451mA    3.413mA
[Power Clamp]
-1.33V    452.7mA    393.2mA    544.5mA
-1.111V   242.2mA    247.6mA    251.2mA
-1.023V   162.6mA    190.6mA    148.4mA
-978.8mV  125.5mA    162.7mA    103.9mA
-934.9mV  91.37mA    135.4mA    68.38mA
-890.9mV  62mA       109.1mA    46.75mA
-847mV    39.66mA    84.12mA    36.27mA
-803mV    26.32mA    61.3mA     30.18mA
-715.1mV  15.66mA    26.54mA    20.71mA
-671.2mV  12.44mA    16.45mA    16.56mA
-407.6mV  911.2uA    1.194mA    1.103mA
2.668V    -5.686mA   -4.559mA   -7.317mA
[Pulldown]
-1.318V   -5.2mA     -3.8mA     -5.5mA
-966.7mV  -13.1mA    -7.8mA     -16.02mA
-834.9mV  -17.24mA   -11.68mA   -16.39mA
-571.2mV  -15.49mA   -15.45mA   -14.56mA
-351.5mV  -11.48mA   -11.33mA   -11.11mA
747mV     20.94mA    20.23mA    20.78mA
1.098V    26.63mA    25.53mA    26.62mA
1.582V    29.15mA    27.77mA    29.11mA
1.933V    25.61mA    22.08mA    27.47mA
2.197V    21.04mA    8.4mA      22.95mA
2.461V    8.1mA      3.9mA      18.4mA
2.68V     4mA        2.9mA      8.8mA
[Pullup]
-1.33V    3.4mA      2.605mA    4.252mA
-1.023V   14.7mA     6.125mA    18.04mA
-890.9mV  22.15mA    10.79mA    20.65mA
-715.1mV  23.66mA    19.86mA    21.56mA
-451.5mV  19.67mA    18.67mA    18.99mA
251.5mV   -9.373mA   -8.927mA   -9.601mA
866.7mV   -22.21mA   -21.56mA   -23.09mA
1.702V    -25.8mA    -24.26mA   -27.63mA
1.965V    -23.67mA   -21.42mA   -26.01mA
2.185V    -22.4mA    -13.26mA   -24.76mA
2.361V    -14.7mA    -9.885mA   -24.23mA
2.668V    -8.6mA     -7.748mA   -10.98mA
[Ramp]
R_load=50.000Ohm
dV/dt_r   472.812mV/103.000ps  447.690mV/127.000ps  499.845mV/89.500ps
dV/dt_f   472.812mV/113.000ps  447.690mV/140.500ps  499.845mV/98.500ps
[Rising waveform]
R_fixture=50.000Ohm
V_fixture=1.350
V_fixture_min=1.283
V_fixture_max=1.450
0s        568.5mV    545.4mV    633.5mV
39ps      581.3mV    542.9mV    674mV
68ps      641.3mV    541.9mV    846.9mV
96ps      783.8mV    543.1mV    1.083V
125ps     982.8mV    548.9mV    1.259V
154ps     1.144V     567.3mV    1.352V
192ps     1.257V     632mV      1.408V
298ps     1.337V     1.084V     1.445V
374ps     1.346V     1.231V     1.449V
938ps     1.35V      1.283V     1.45V
[Rising waveform]
R_fixture=50.000Ohm
V_fixture=0
0s        46.14mV    41.25mV    66.34mV
39ps      41.5mV     39.65mV    77.66mV
77ps      87.92mV    36.17mV    220.3mV
163ps     447.8mV    32.56mV    679.1mV
211ps     629.3mV    83.8mV     808.8mV
259ps     739.1mV    203.9mV    871.1mV
374ps     832.1mV    586.4mV    917.3mV
470ps     849mV      732.2mV    926.2mV
614ps     855.5mV    787.8mV    929.4mV
938ps     857.3mV    801.2mV    929.9mV
[Falling waveform]
R_fixture=50.000Ohm
V_fixture=1.350
V_fixture_min=1.283
V_fixture_max=1.450
0s        1.355V     1.282V     1.456V
48ps      1.361V     1.284V     1.438V
87ps      1.312V     1.29V      1.307V
183ps     955.2mV    1.283V     871.3mV
221ps     823.6mV    1.235V     772.8mV
269ps     711.7mV    1.115V     705.8mV
393ps     607.6mV    763mV      653.4mV
489ps     589.4mV    629.9mV    645.8mV
642ps     581.9mV    571.4mV    642.5mV
938ps     579.2mV    554.5mV    641.5mV
[Falling waveform]
R_fixture=50.000Ohm
V_fixture=0
0s        869.8mV    805.5mV    938.6mV
29ps      859mV      809.5mV    910.9mV
58ps      794.1mV    813.9mV    768.4mV
106ps     533mV      812.1mV    401.1mV
135ps     356.9mV    790.6mV    255.3mV
163ps     234.6mV    740.7mV    175.4mV
202ps     139.9mV    610.2mV    121.1mV
288ps     72.33mV    236.6mV    83.03mV
374ps     58.38mV    90.5mV     74.78mV
938ps     52.38mV    41.03mV    72.26mV
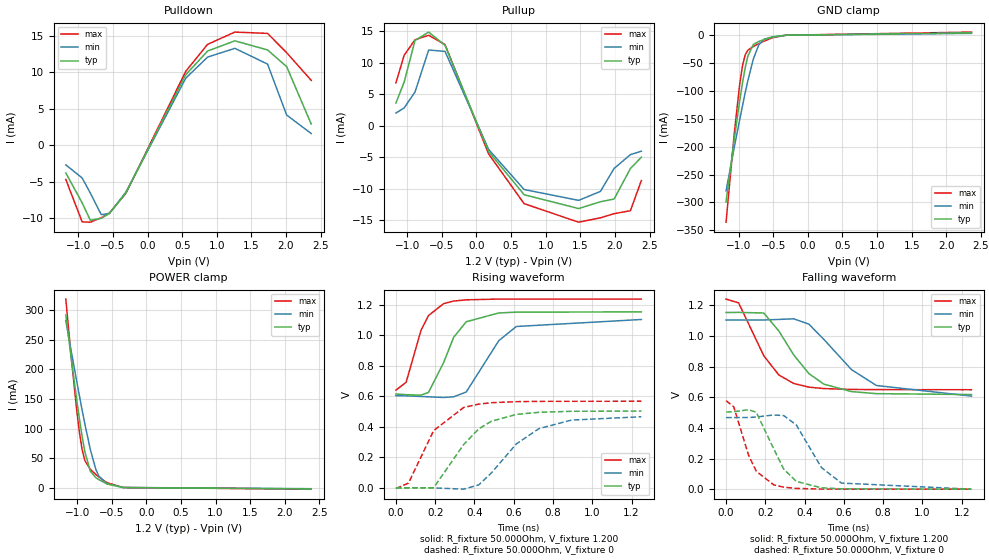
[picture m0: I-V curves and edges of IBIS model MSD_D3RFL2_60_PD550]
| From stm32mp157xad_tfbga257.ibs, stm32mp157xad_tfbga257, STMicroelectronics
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[Model] MSD_D3RFL2_60_PD550
Model_type   I/O
C_comp 2.431pF   2.345pF   2.556pF
Vinh = 820.000mV
Vinl = 380.000mV
Vmeas = 600.000mV
Vref = 600.000mV
[Model Spec]
Vinh   820.000mV   790.000mV   870.000mV
Vinl   380.000mV   350.000mV   430.000mV
Vmeas   600.000mV   570.000mV   650.000mV
Vref   600.000mV   570.000mV   650.000mV
[Temperature Range]   25.000   125.000   -40.000
[Voltage Range]   1.200V   1.140V   1.300V
[GND Clamp Reference]   0.00V   0.00V   0.00V
[Pulldown Reference]   0.00V   0.00V   0.00V
[POWER Clamp Reference]   1.200V   1.140V   1.300V
[Pullup Reference]   1.200V   1.140V   1.300V
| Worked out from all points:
|   slope of the pulldown table from 0 to 0.18 V, typ, clamps not added: 50.1 ohm
|   slope of the pullup table from 0 to 0.18 V, typ, clamps not added: 42.9 ohm
|   GND clamp passes 1 mA (typ) near -0.40 V on its own axis
|   POWER clamp passes 1 mA (typ) near -0.41 V on its own axis
|   rising waveform, R_fixture 50.000Ohm, V_fixture 1.200: 20-80 % time 109ps typ, 140ps min, 90.8ps max; typ from 0.616 V to 1.16 V
|   rising waveform, R_fixture 50.000Ohm, V_fixture 0: 20-80 % time 180ps typ, 222ps min, 150ps max; typ from 0.001 V to 0.504 V
|   falling waveform, R_fixture 50.000Ohm, V_fixture 1.200: 20-80 % time 188ps typ, 238ps min, 149ps max; typ from 1.15 V to 0.618 V
|   falling waveform, R_fixture 50.000Ohm, V_fixture 0: 20-80 % time 111ps typ, 137ps min, 94.4ps max; typ from 0.504 V to 0 V
[GND Clamp]
-1.182V   -299.4mA   -279.4mA   -335.5mA
-1.064V   -187.2mA   -201.7mA   -177.2mA
-984.9mV  -117.7mA   -151.5mA   -88.38mA
-945.5mV  -86.38mA   -127.3mA   -55.57mA
-906.1mV  -58.98mA   -103.8mA   -35.45mA
-866.7mV  -37.48mA   -81.61mA   -27.05mA
-787.9mV  -16.83mA   -42.88mA   -20.43mA
-709.1mV  -11.34mA   -17.45mA   -15.32mA
-630.3mV  -7.809mA   -7.49mA    -10.62mA
-512.1mV  -3.532mA   -3.013mA   -4.68mA
-315.1mV  -161.1uA   -227.4uA   -151.1uA
2.364V    4.162mA    3.192mA    5.446mA
[Power Clamp]
-1.164V   292.2mA    282.4mA    319.1mA
-1.085V   218.5mA    230.7mA    219.9mA
-1.006V   148.3mA    179.9mA    131mA
-966.7mV  115.8mA    155mA      93.19mA
-927.3mV  85.99mA    130.7mA    63.83mA
-887.9mV  60.26mA    107.3mA    45.72mA
-809.1mV  27.71mA    64.21mA    31.02mA
-730.3mV  16.94mA    31.06mA    22.31mA
-690.9mV  13.86mA    20.24mA    18.46mA
-572.7mV  6.594mA    6.506mA    8.718mA
-336.4mV  182.6uA    351.4uA    213.2uA
2.382V    -2.141mA   -1.766mA   -2.539mA
[Pulldown]
-1.182V   -3.8mA     -2.7mA     -4.7mA
-945.5mV  -7.91mA    -4.5mA     -10.52mA
-827.3mV  -10.3mA    -6.57mA    -10.56mA
-669.7mV  -10.02mA   -9.53mA    -9.95mA
-551.5mV  -9.367mA   -9.335mA   -9.299mA
-315.1mV  -6.567mA   -6.465mA   -6.607mA
551.5mV   9.676mA    9.198mA    10.14mA
866.7mV   12.92mA    12.09mA    13.84mA
1.261V    14.32mA    13.29mA    15.52mA
1.733V    13.07mA    11.13mA    15.34mA
2.009V    10.78mA    4.14mA     12.69mA
2.364V    2.9mA      1.6mA      8.9mA
[Pullup]
-1.164V   3.6mA      2.005mA    6.785mA
-1.045V   6.9mA      2.809mA    11.16mA
-887.9mV  13.51mA    5.344mA    13.62mA
-690.9mV  14.83mA    11.99mA    14.32mA
-454.5mV  12.73mA    11.77mA    12.85mA
175.8mV   -4.108mA   -3.772mA   -4.491mA
687.9mV   -10.94mA   -10.12mA   -12.36mA
1.476V    -13.14mA   -11.84mA   -15.3mA
1.791V    -12.06mA   -10.42mA   -14.61mA
1.988V    -11.63mA   -6.784mA   -13.95mA
2.224V    -6.8mA     -4.595mA   -13.48mA
2.382V    -5mA       -4.048mA   -8.7mA
[Ramp]
R_load=50.000Ohm
dV/dt_r   312.390mV/145.000ps  290.369mV/182.000ps  347.550mV/120.000ps
dV/dt_f   312.360mV/150.000ps  290.310mV/190.000ps  347.550mV/122.000ps
[Rising waveform]
R_fixture=50.000Ohm
V_fixture=1.200
V_fixture_min=1.140
V_fixture_max=1.300
0s        616mV      605.3mV    641.5mV
52ps      611.8mV    604mV      692.9mV
128ps     608.5mV    600mV      1.035V
166ps     626.6mV    597.5mV    1.131V
243ps     822.4mV    593.4mV    1.209V
294ps     987.7mV    597.6mV    1.226V
358ps     1.09V      629.2mV    1.234V
524ps     1.148V     966.1mV    1.239V
613ps     1.153V     1.059V     1.239V
1.25ns    1.155V     1.105V     1.239V
[Rising waveform]
R_fixture=50.000Ohm
V_fixture=0
0s        587.6uV    133.6uV    -3.675mV
64ps      194uV      481.2uV    31.74mV
192ps     941.7uV    203.9uV    375.9mV
345ps     284.2mV    -8.226mV   527.9mV
422ps     387.7mV    19.82mV    549.8mV
486ps     437.2mV    97.97mV    558.9mV
613ps     482mV      288.3mV    565.9mV
728ps     496mV      388.7mV    567.7mV
894ps     502.6mV    445.1mV    568.3mV
1.25ns    504.2mV    466.9mV    568.6mV
[Falling waveform]
R_fixture=50.000Ohm
V_fixture=1.200
V_fixture_min=1.140
V_fixture_max=1.300
0s        1.154V     1.105V     1.242V
64ps      1.155V     1.105V     1.217V
192ps     1.151V     1.105V     871.9mV
269ps     1.033V     1.109V     745.8mV
345ps     876.3mV    1.113V     690.3mV
422ps     755mV      1.078V     666.7mV
498ps     686.2mV    978.6mV    657.2mV
639ps     637.4mV    781.1mV    651.6mV
766ps     624mV      677.3mV    650.4mV
1.25ns    618.1mV    608.1mV    649.6mV
[Falling waveform]
R_fixture=50.000Ohm
V_fixture=0
0s        503.8mV    467.9mV    578.2mV
39ps      506.2mV    467.6mV    538.9mV
115ps     518.9mV    468.4mV    220.5mV
154ps     502.4mV    471.5mV    117.1mV
243ps     262.8mV    484.8mV    28.01mV
294ps     130.6mV    480.6mV    12.82mV
358ps     50.52mV    419.1mV    4.962mV
486ps     8.947mV    140.8mV    676.5uV
588ps     2.205mV    39.68mV    122uV
1.25ns    -3.605uV   14.73uV    1.71uV
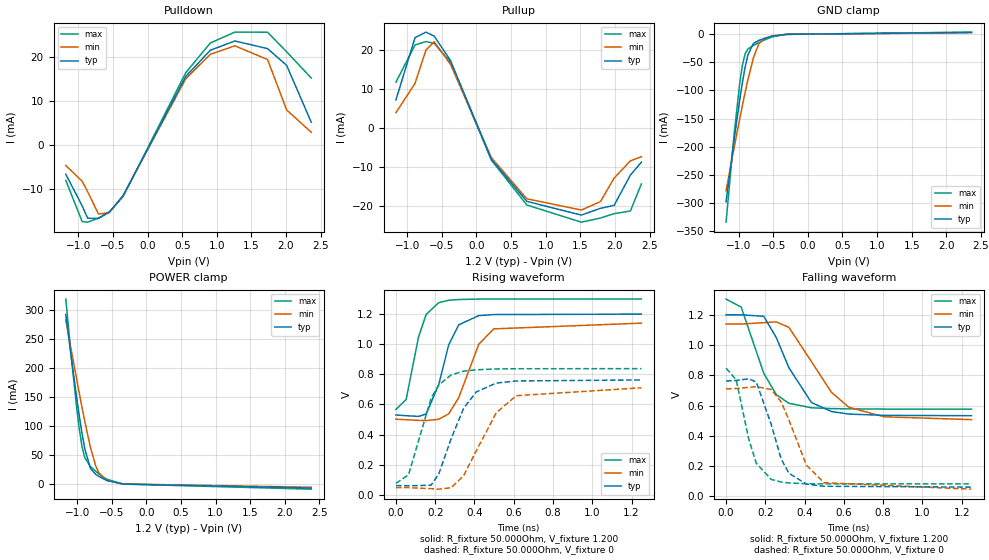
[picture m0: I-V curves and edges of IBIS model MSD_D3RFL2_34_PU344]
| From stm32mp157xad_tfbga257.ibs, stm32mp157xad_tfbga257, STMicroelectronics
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[Model] MSD_D3RFL2_34_PU344
Model_type   I/O
C_comp 2.348pF   2.261pF   2.473pF
Vinh = 820.000mV
Vinl = 380.000mV
Vmeas = 600.000mV
Vref = 600.000mV
[Model Spec]
Vinh   820.000mV   790.000mV   870.000mV
Vinl   380.000mV   350.000mV   430.000mV
Vmeas   600.000mV   570.000mV   650.000mV
Vref   600.000mV   570.000mV   650.000mV
[Temperature Range]   25.000   125.000   -40.000
[Voltage Range]   1.200V   1.140V   1.300V
[GND Clamp Reference]   0.00V   0.00V   0.00V
[Pulldown Reference]   0.00V   0.00V   0.00V
[POWER Clamp Reference]   1.200V   1.140V   1.300V
[Pullup Reference]   1.200V   1.140V   1.300V
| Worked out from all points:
|   slope of the pulldown table from 0 to 0.18 V, typ, clamps not added: 31.3 ohm
|   slope of the pullup table from 0 to 0.18 V, typ, clamps not added: 26.5 ohm
|   GND clamp passes 1 mA (typ) near -0.41 V on its own axis
|   POWER clamp passes 1 mA (typ) near -0.41 V on its own axis
|   rising waveform, R_fixture 50.000Ohm, V_fixture 1.200: 20-80 % time 85.8ps typ, 114ps min, 71.8ps max; typ from 0.53 V to 1.2 V
|   rising waveform, R_fixture 50.000Ohm, V_fixture 0: 20-80 % time 130ps typ, 163ps min, 109ps max; typ from 0.061 V to 0.763 V
|   falling waveform, R_fixture 50.000Ohm, V_fixture 1.200: 20-80 % time 149ps typ, 195ps min, 124ps max; typ from 1.2 V to 0.533 V
|   falling waveform, R_fixture 50.000Ohm, V_fixture 0: 20-80 % time 96.8ps typ, 124ps min, 82.6ps max; typ from 0.762 V to 0.06 V
[GND Clamp]
-1.182V   -298.5mA   -278.7mA   -334.6mA
-1.064V   -186.4mA   -201mA     -176.4mA
-984.9mV  -117.1mA   -150.9mA   -87.65mA
-945.5mV  -85.8mA    -126.7mA   -54.89mA
-906.1mV  -58.45mA   -103.4mA   -34.82mA
-866.7mV  -36.99mA   -81.15mA   -26.46mA
-787.9mV  -16.43mA   -42.51mA   -19.96mA
-709.1mV  -11.02mA   -17.14mA   -14.94mA
-630.3mV  -7.563mA   -7.255mA   -10.33mA
-512.1mV  -3.391mA   -2.874mA   -4.513mA
-315.1mV  -135.6uA   -195uA     -130uA
2.364V    3.306mA    2.793mA    3.888mA
[Power Clamp]
-1.164V   291.7mA    282.1mA    318.2mA
-1.085V   217.9mA    230.5mA    219.1mA
-1.006V   147.8mA    179.6mA    130.3mA
-966.7mV  115.4mA    154.8mA    92.58mA
-927.3mV  85.61mA    130.5mA    63.27mA
-887.9mV  59.92mA    107mA      45.21mA
-809.1mV  27.42mA    64.02mA    30.59mA
-730.3mV  16.72mA    30.92mA    21.98mA
-690.9mV  13.66mA    20.11mA    18.17mA
-572.7mV  6.48mA     6.432mA    8.549mA
-336.4mV  188.5uA    360.2uA    208.2uA
2.382V    -6.618mA   -5.26mA    -8.576mA
[Pulldown]
-1.182V   -6.7mA     -4.7mA     -8.1mA
-945.5mV  -13.93mA   -8.3mA     -17.52mA
-866.7mV  -16.74mA   -10.69mA   -17.66mA
-709.1mV  -16.81mA   -15.8mA    -16.7mA
-551.5mV  -15.32mA   -15.48mA   -15.28mA
-354.6mV  -11.64mA   -11.56mA   -11.82mA
551.5mV   15.66mA    15.14mA    16.51mA
906.1mV   21.64mA    20.72mA    23.3mA
1.261V    23.76mA    22.65mA    25.79mA
1.733V    22.01mA    19.52mA    25.76mA
2.009V    18.18mA    7.99mA     21.28mA
2.364V    5.2mA      2.9mA      15.3mA
[Pullup]
-1.164V   7.3mA      4.009mA    11.85mA
-887.9mV  23.27mA    11.54mA    21.41mA
-730.3mV  24.71mA    20.07mA    22.27mA
-612.1mV  23.69mA    22.22mA    21.84mA
-375.8mV  17.41mA    16.45mA    16.97mA
215.2mV   -7.946mA   -7.528mA   -8.167mA
727.3mV   -18.75mA   -18.09mA   -19.68mA
1.515V    -22.28mA   -20.98mA   -24.1mA
1.791V    -20.54mA   -18.82mA   -23.03mA
1.988V    -19.79mA   -12.79mA   -21.91mA
2.224V    -12mA      -8.343mA   -21.22mA
2.382V    -8.7mA     -7.295mA   -14.29mA
[Ramp]
R_load=50.000Ohm
dV/dt_r   410.958mV/108.000ps  389.622mV/139.000ps  443.955mV/90.500ps
dV/dt_f   410.958mV/123.500ps  389.559mV/161.000ps  443.955mV/103.500ps
[Rising waveform]
R_fixture=50.000Ohm
V_fixture=1.200
V_fixture_min=1.140
V_fixture_max=1.300
0s        530.1mV    501.7mV    566.7mV
52ps      525.1mV    498.5mV    632.8mV
115ps     520.5mV    494.3mV    1.047V
154ps     536mV      492.7mV    1.198V
218ps     731.7mV    501.6mV    1.276V
269ps     996.8mV    537.4mV    1.292V
320ps     1.129V     645.7mV    1.297V
422ps     1.19V      999.5mV    1.3V
498ps     1.197V     1.102V     1.3V
1.25ns    1.2V       1.14V      1.3V
[Rising waveform]
R_fixture=50.000Ohm
V_fixture=0
0s        60.99mV    47.45mV    75.82mV
64ps      59.44mV    47.1mV     132.2mV
179ps     63.35mV    40.53mV    640.8mV
218ps     137.3mV    37.09mV    729.4mV
281ps     371.8mV    46.65mV    796.2mV
345ps     574.9mV    126.8mV    821.1mV
409ps     682.9mV    291.4mV    830.2mV
511ps     741.8mV    544.6mV    835.7mV
613ps     756mV      658mV      837.2mV
1.25ns    762.7mV    710.6mV    837.7mV
[Falling waveform]
R_fixture=50.000Ohm
V_fixture=1.200
V_fixture_min=1.140
V_fixture_max=1.300
0s        1.2V       1.139V     1.304V
77ps      1.2V       1.139V     1.251V
192ps     1.19V      1.148V     813.4mV
256ps     1.049V     1.153V     672mV
320ps     850mV      1.117V     614.8mV
435ps     620.1mV    890.4mV    585.1mV
537ps     560.2mV    686.9mV    579.5mV
626ps     543.4mV    588mV      577.9mV
805ps     535.1mV    525.5mV    576.5mV
1.25ns    532.6mV    506.7mV    576.3mV
[Falling waveform]
R_fixture=50.000Ohm
V_fixture=0
0s        762.1mV    710.2mV    847mV
52ps      766.2mV    712.5mV    769.3mV
115ps     776.6mV    719.9mV    381mV
154ps     755.9mV    724.9mV    218.5mV
230ps     475.5mV    706.4mV    111.6mV
281ps     245.1mV    623.7mV    93.84mV
320ps     152.6mV    505mV      87.96mV
409ps     80.46mV    206.5mV    83.09mV
498ps     66.14mV    89.7mV     81.97mV
1.25ns    60.35mV    46.92mV    81.65mV
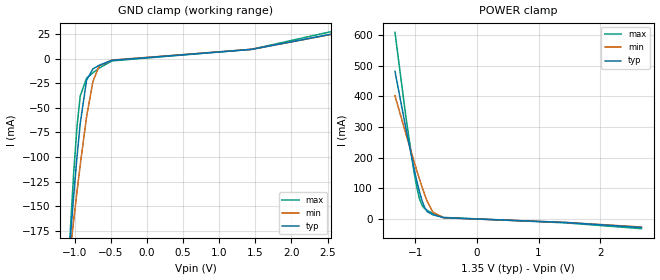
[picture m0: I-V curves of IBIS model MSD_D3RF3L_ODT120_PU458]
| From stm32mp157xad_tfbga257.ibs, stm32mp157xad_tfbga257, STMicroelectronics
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[Model] MSD_D3RF3L_ODT120_PU458
Model_type   Input
C_comp 2.354pF   2.275pF   2.445pF
Vinh = 810.000mV
Vinl = 540.000mV
[Temperature Range]   25.000   125.000   -40.000
[Voltage Range]   1.350V   1.283V   1.450V
[GND Clamp Reference]   0.00V   0.00V   0.00V
[POWER Clamp Reference]   1.350V   1.283V   1.450V
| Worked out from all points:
|   GND clamp passes 1 mA (typ) near -0.43 V on its own axis
|   POWER clamp passes 1 mA (typ) near -0.31 V on its own axis
[GND Clamp]
-1.318V   -446.3mA   -371.3mA   -564.8mA
-1.098V   -221.2mA   -221mA     -229.6mA
-1.055V   -178.6mA   -191.9mA   -169mA
-1.011V   -137.7mA   -163.2mA   -114.2mA
-966.7mV  -99.76mA   -135.2mA   -69.05mA
-922.7mV  -66.25mA   -108.3mA   -38.17mA
-834.9mV  -22.13mA   -59.42mA   -19.99mA
-747mV    -10.55mA   -23.38mA   -14.48mA
-659.1mV  -6.822mA   -7.302mA   -9.674mA
-483.3mV  -1.827mA   -1.543mA   -2.378mA
1.45V     9.287mA    9.367mA    9.417mA
2.68V     26.56mA    26.32mA    29.49mA
[Power Clamp]
-1.33V    481.5mA    402mA      608.2mA
-1.155V   297.8mA    279.5mA    336.3mA
-1.023V   166.6mA    189.6mA    156.3mA
-978.8mV  126.9mA    160.5mA    107mA
-934.9mV  90.99mA    132.1mA    68.18mA
-890.9mV  60.47mA    104.8mA    44.99mA
-847mV    37.57mA    79.26mA    34.09mA
-803mV    24.2mA     56.31mA    28mA
-715.1mV  14.14mA    22.88mA    18.8mA
-539.4mV  4.894mA    4.606mA    5.809mA
1.438V    -10.61mA   -10.47mA   -11.84mA
2.668V    -26.89mA   -25.45mA   -30.76mA
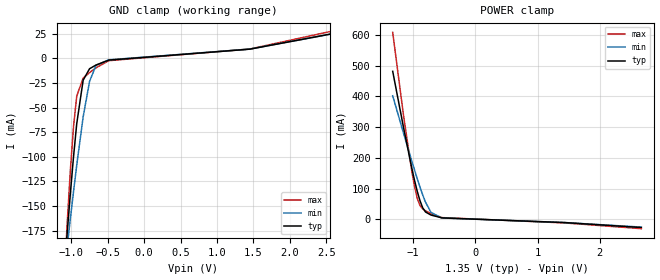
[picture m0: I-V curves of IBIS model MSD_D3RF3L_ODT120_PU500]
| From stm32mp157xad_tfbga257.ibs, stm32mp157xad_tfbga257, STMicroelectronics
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[Model] MSD_D3RF3L_ODT120_PU500
Model_type   Input
C_comp 2.371pF   2.291pF   2.461pF
Vinh = 810.000mV
Vinl = 540.000mV
[Temperature Range]   25.000   125.000   -40.000
[Voltage Range]   1.350V   1.283V   1.450V
[GND Clamp Reference]   0.00V   0.00V   0.00V
[POWER Clamp Reference]   1.350V   1.283V   1.450V
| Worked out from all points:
|   GND clamp passes 1 mA (typ) near -0.43 V on its own axis
|   POWER clamp passes 1 mA (typ) near -0.31 V on its own axis
[GND Clamp]
-1.318V   -446.5mA   -371.3mA   -565.1mA
-1.098V   -221.4mA   -221.2mA   -229.8mA
-1.055V   -178.6mA   -191.9mA   -169.1mA
-1.011V   -137.8mA   -163.2mA   -114.4mA
-966.7mV  -99.78mA   -135.3mA   -69.18mA
-922.7mV  -66.32mA   -108.3mA   -38.3mA
-834.9mV  -22.2mA    -59.48mA   -20.1mA
-747mV    -10.6mA    -23.42mA   -14.56mA
-659.1mV  -6.862mA   -7.331mA   -9.739mA
-483.3mV  -1.846mA   -1.557mA   -2.409mA
1.45V     9.269mA    9.342mA    9.417mA
2.68V     26.32mA    26.12mA    29.21mA
[Power Clamp]
-1.33V    481.7mA    402.2mA    608.4mA
-1.155V   297.9mA    279.6mA    336.4mA
-1.023V   166.7mA    189.7mA    156.4mA
-978.8mV  127mA      160.6mA    107.1mA
-934.9mV  91.06mA    132.2mA    68.29mA
-890.9mV  60.54mA    104.9mA    45.07mA
-847mV    37.63mA    79.34mA    34.17mA
-803mV    24.26mA    56.36mA    28.07mA
-715.1mV  14.19mA    22.91mA    18.85mA
-539.4mV  4.922mA    4.625mA    5.834mA
1.438V    -10.35mA   -10.26mA   -11.51mA
2.668V    -26.41mA   -25.07mA   -30.11mA
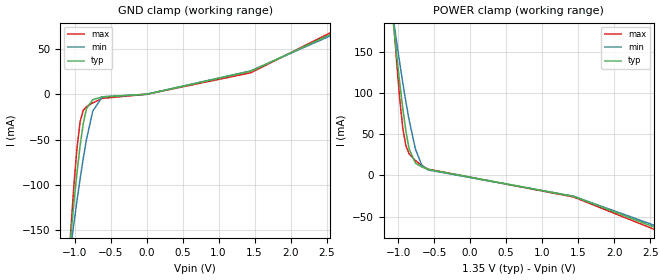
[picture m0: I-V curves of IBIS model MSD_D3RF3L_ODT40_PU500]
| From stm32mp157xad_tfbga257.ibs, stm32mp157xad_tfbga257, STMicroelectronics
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[Model] MSD_D3RF3L_ODT40_PU500
Model_type   Input
C_comp 2.350pF   2.310pF   2.402pF
Vinh = 810.000mV
Vinl = 540.000mV
[Temperature Range]   25.000   125.000   -40.000
[Voltage Range]   1.350V   1.283V   1.450V
[GND Clamp Reference]   0.00V   0.00V   0.00V
[POWER Clamp Reference]   1.350V   1.283V   1.450V
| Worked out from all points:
|   GND clamp passes 1 mA (typ) near -0.47 V on its own axis
|   POWER clamp passes 1 mA (typ) near -0.15 V on its own axis
[GND Clamp]
-1.318V   -415.5mA   -341.4mA   -533.5mA
-1.055V   -159.3mA   -170.5mA   -153.5mA
-1.011V   -121.7mA   -143.7mA   -102.7mA
-966.7mV  -87.28mA   -117.9mA   -59.96mA
-922.7mV  -56.74mA   -93.51mA   -30.28mA
-878.8mV  -32.13mA   -70.69mA   -17.63mA
-834.9mV  -15.99mA   -50.14mA   -13.66mA
-747mV    -6.044mA   -18.54mA   -9.508mA
-615.1mV  -2.858mA   -2.824mA   -4.516mA
200nV     3.387nA    3.254nA    3.446nA
1.45V     25.56mA    25.96mA    23.83mA
2.68V     70.76mA    69.03mA    73.11mA
[Power Clamp]
-1.33V    441.1mA    363.8mA    566.2mA
-1.067V   185.1mA    190.4mA    192.6mA
-1.023V   147.8mA    163.2mA    140.3mA
-978.8mV  113mA      136.9mA    93.57mA
-934.9mV  80.87mA    111.9mA    56.79mA
-890.9mV  52.98mA    88.45mA    35.34mA
-847mV    31.87mA    66.94mA    26.01mA
-759.1mV  14.71mA    31.67mA    17.83mA
-671.2mV  10.18mA    12.29mA    11.93mA
-583.3mV  7.223mA    6.477mA    7.446mA
1.438V    -25.56mA   -25.31mA   -26.3mA
2.668V    -66.38mA   -64.06mA   -69.39mA
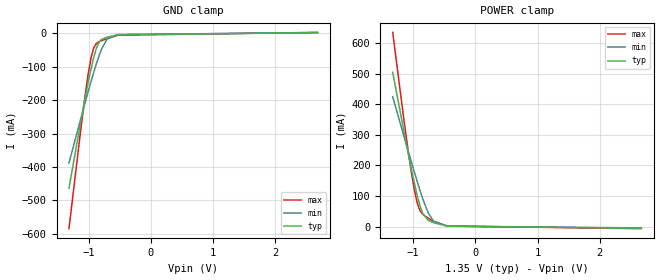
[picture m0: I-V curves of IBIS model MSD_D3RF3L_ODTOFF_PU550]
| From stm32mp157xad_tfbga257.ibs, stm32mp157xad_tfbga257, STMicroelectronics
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[Model] MSD_D3RF3L_ODTOFF_PU550
Model_type   Input
C_comp 2.425pF   2.340pF   2.550pF
Vinh = 810.000mV
Vinl = 540.000mV
[Temperature Range]   25.000   125.000   -40.000
[Voltage Range]   1.350V   1.283V   1.450V
[GND Clamp Reference]   0.00V   0.00V   0.00V
[POWER Clamp Reference]   1.350V   1.283V   1.450V
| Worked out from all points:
|   GND clamp passes 1 mA (typ) near -0.40 V on its own axis
|   POWER clamp passes 1 mA (typ) near -0.41 V on its own axis
[GND Clamp]
-1.318V   -463.9mA   -388.4mA   -585mA
-1.142V   -279.5mA   -265.2mA   -309.8mA
-1.055V   -191mA     -204.9mA   -181.6mA
-1.011V   -148.8mA   -175.5mA   -124.5mA
-966.7mV  -109.2mA   -146.7mA   -76.94mA
-922.7mV  -73.9mA    -118.7mA   -44.73mA
-878.8mV  -45.38mA   -92.14mA   -30.52mA
-834.9mV  -26.75mA   -67.51mA   -25.27mA
-790.9mV  -17.86mA   -45.84mA   -21.83mA
-703mV    -11.44mA   -16.66mA   -15.74mA
-527.3mV  -4.097mA   -3.44mA    -5.533mA
2.68V     2.422mA    2.055mA    2.872mA
[Power Clamp]
-1.33V    504.3mA    424.3mA    634.3mA
-1.155V   317.1mA    299mA      356.9mA
-1.067V   225.7mA    237.3mA    227.1mA
-1.023V   181.5mA    206.8mA    168.7mA
-978.8mV  139.5mA    176.7mA    117.3mA
-934.9mV  100.9mA    147.1mA    77mA
-890.9mV  67.79mA    118.5mA    52.58mA
-847mV    43.02mA    91.39mA    40.64mA
-759.1mV  21.2mA     45.07mA    27.89mA
-671.2mV  13.27mA    17.55mA    18.05mA
-451.5mV  1.907mA    2.151mA    2.405mA
2.668V    -4.778mA   -3.823mA   -6.152mA
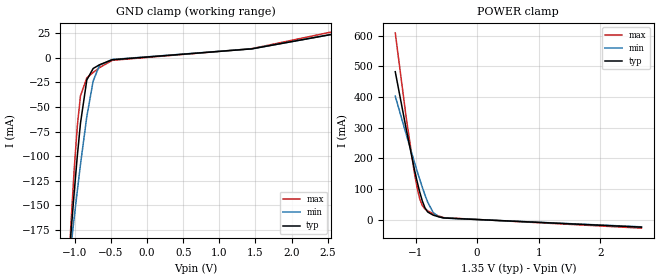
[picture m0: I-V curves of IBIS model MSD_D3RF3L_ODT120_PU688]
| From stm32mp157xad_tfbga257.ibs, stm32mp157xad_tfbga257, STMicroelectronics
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[Model] MSD_D3RF3L_ODT120_PU688
Model_type   Input
C_comp 2.412pF   2.333pF   2.504pF
Vinh = 810.000mV
Vinl = 540.000mV
[Temperature Range]   25.000   125.000   -40.000
[Voltage Range]   1.350V   1.283V   1.450V
[GND Clamp Reference]   0.00V   0.00V   0.00V
[POWER Clamp Reference]   1.350V   1.283V   1.450V
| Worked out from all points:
|   GND clamp passes 1 mA (typ) near -0.43 V on its own axis
|   POWER clamp passes 1 mA (typ) near -0.31 V on its own axis
[GND Clamp]
-1.318V   -446.9mA   -371.8mA   -565.6mA
-1.098V   -221.7mA   -221.4mA   -230.2mA
-1.055V   -178.9mA   -192.2mA   -169.5mA
-1.011V   -138.1mA   -163.5mA   -114.9mA
-966.7mV  -100mA     -135.5mA   -69.53mA
-922.7mV  -66.57mA   -108.5mA   -38.62mA
-834.9mV  -22.4mA    -59.64mA   -20.36mA
-747mV    -10.76mA   -23.56mA   -14.78mA
-659.1mV  -6.976mA   -7.43mA    -9.901mA
-483.3mV  -1.885mA   -1.601mA   -2.478mA
1.45V     9.214mA    9.268mA    9.417mA
2.68V     25.58mA    25.5mA     28.34mA
[Power Clamp]
-1.33V    482.2mA    402.6mA    608.9mA
-1.155V   298.3mA    279.9mA    336.8mA
-1.023V   167mA      190mA      156.7mA
-978.8mV  127.2mA    160.8mA    107.4mA
-934.9mV  91.28mA    132.4mA    68.59mA
-890.9mV  60.77mA    105.1mA    45.37mA
-847mV    37.84mA    79.52mA    34.44mA
-803mV    24.44mA    56.51mA    28.31mA
-715.1mV  14.33mA    23.04mA    19.03mA
-627.3mV  8.941mA    9.093mA    11.55mA
-539.4mV  4.99mA     4.683mA    5.917mA
2.668V    -24.97mA   -23.92mA   -28.25mA
